VERSION 5.8 ;
BUSBITCHARS "[]" ;
DIVIDERCHAR "/" ;
UNITS
    DATABASE MICRONS 1000 ;
END UNITS

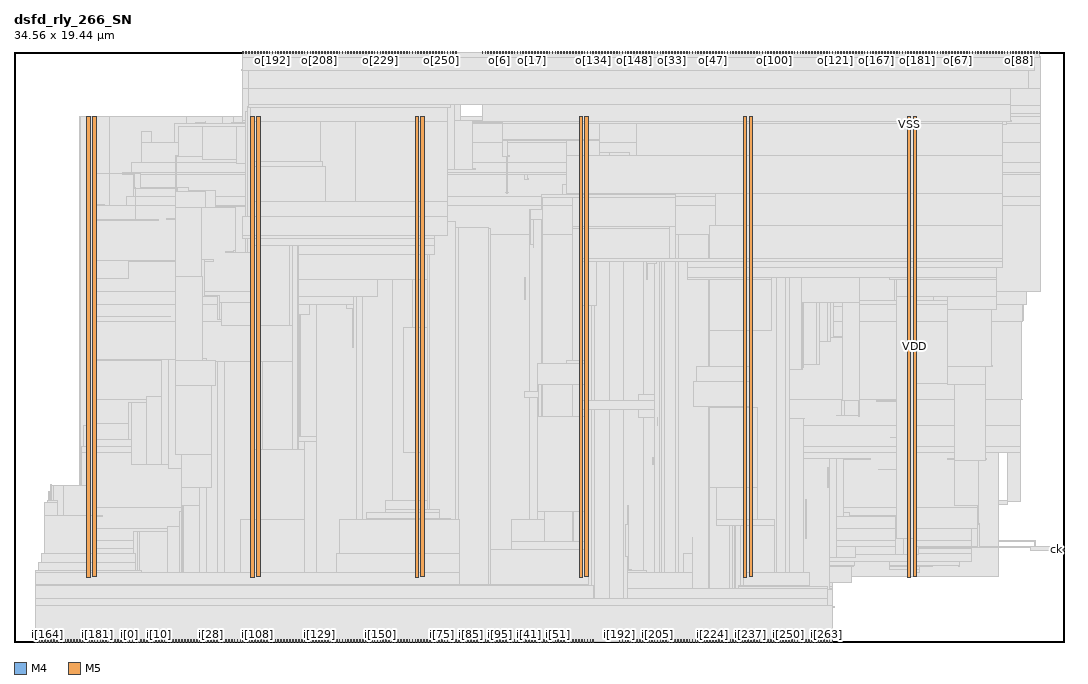
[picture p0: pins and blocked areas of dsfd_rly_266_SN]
MACRO dsfd_rly_266_SN
  FOREIGN dsfd_rly_266_SN 0 0 ;
  CLASS BLOCK ;
  SIZE 34.56 BY 19.44 ;
  PIN ck
    DIRECTION INPUT ;
    USE SIGNAL ;
    PORT
      LAYER M4 ;
        RECT  34.476 3.024 34.56 3.048 ;
    END
  END ck
  PIN i[0]
    DIRECTION INPUT ;
    USE SIGNAL ;
    PORT
      LAYER M5 ;
        RECT  3.792 0 3.816 0.084 ;
    END
  END i[0]
  PIN i[100]
    DIRECTION INPUT ;
    USE SIGNAL ;
    PORT
      LAYER M5 ;
        RECT  7.248 0 7.272 0.084 ;
    END
  END i[100]
  PIN i[101]
    DIRECTION INPUT ;
    USE SIGNAL ;
    PORT
      LAYER M5 ;
        RECT  7.344 0 7.368 0.084 ;
    END
  END i[101]
  PIN i[102]
    DIRECTION INPUT ;
    USE SIGNAL ;
    PORT
      LAYER M5 ;
        RECT  7.44 0 7.464 0.084 ;
    END
  END i[102]
  PIN i[103]
    DIRECTION INPUT ;
    USE SIGNAL ;
    PORT
      LAYER M5 ;
        RECT  7.536 0 7.56 0.084 ;
    END
  END i[103]
  PIN i[104]
    DIRECTION INPUT ;
    USE SIGNAL ;
    PORT
      LAYER M5 ;
        RECT  7.632 0 7.656 0.084 ;
    END
  END i[104]
  PIN i[105]
    DIRECTION INPUT ;
    USE SIGNAL ;
    PORT
      LAYER M5 ;
        RECT  7.728 0 7.752 0.084 ;
    END
  END i[105]
  PIN i[106]
    DIRECTION INPUT ;
    USE SIGNAL ;
    PORT
      LAYER M5 ;
        RECT  7.824 0 7.848 0.084 ;
    END
  END i[106]
  PIN i[107]
    DIRECTION INPUT ;
    USE SIGNAL ;
    PORT
      LAYER M5 ;
        RECT  7.92 0 7.944 0.084 ;
    END
  END i[107]
  PIN i[108]
    DIRECTION INPUT ;
    USE SIGNAL ;
    PORT
      LAYER M5 ;
        RECT  8.016 0 8.04 0.084 ;
    END
  END i[108]
  PIN i[109]
    DIRECTION INPUT ;
    USE SIGNAL ;
    PORT
      LAYER M5 ;
        RECT  8.112 0 8.136 0.084 ;
    END
  END i[109]
  PIN i[10]
    DIRECTION INPUT ;
    USE SIGNAL ;
    PORT
      LAYER M5 ;
        RECT  4.752 0 4.776 0.084 ;
    END
  END i[10]
  PIN i[110]
    DIRECTION INPUT ;
    USE SIGNAL ;
    PORT
      LAYER M5 ;
        RECT  8.208 0 8.232 0.084 ;
    END
  END i[110]
  PIN i[111]
    DIRECTION INPUT ;
    USE SIGNAL ;
    PORT
      LAYER M5 ;
        RECT  8.304 0 8.328 0.084 ;
    END
  END i[111]
  PIN i[112]
    DIRECTION INPUT ;
    USE SIGNAL ;
    PORT
      LAYER M5 ;
        RECT  8.4 0 8.424 0.084 ;
    END
  END i[112]
  PIN i[113]
    DIRECTION INPUT ;
    USE SIGNAL ;
    PORT
      LAYER M5 ;
        RECT  8.496 0 8.52 0.084 ;
    END
  END i[113]
  PIN i[114]
    DIRECTION INPUT ;
    USE SIGNAL ;
    PORT
      LAYER M5 ;
        RECT  8.592 0 8.616 0.084 ;
    END
  END i[114]
  PIN i[115]
    DIRECTION INPUT ;
    USE SIGNAL ;
    PORT
      LAYER M5 ;
        RECT  8.688 0 8.712 0.084 ;
    END
  END i[115]
  PIN i[116]
    DIRECTION INPUT ;
    USE SIGNAL ;
    PORT
      LAYER M5 ;
        RECT  8.784 0 8.808 0.084 ;
    END
  END i[116]
  PIN i[117]
    DIRECTION INPUT ;
    USE SIGNAL ;
    PORT
      LAYER M5 ;
        RECT  8.88 0 8.904 0.084 ;
    END
  END i[117]
  PIN i[118]
    DIRECTION INPUT ;
    USE SIGNAL ;
    PORT
      LAYER M5 ;
        RECT  8.976 0 9 0.084 ;
    END
  END i[118]
  PIN i[119]
    DIRECTION INPUT ;
    USE SIGNAL ;
    PORT
      LAYER M5 ;
        RECT  9.072 0 9.096 0.084 ;
    END
  END i[119]
  PIN i[11]
    DIRECTION INPUT ;
    USE SIGNAL ;
    PORT
      LAYER M5 ;
        RECT  4.848 0 4.872 0.084 ;
    END
  END i[11]
  PIN i[120]
    DIRECTION INPUT ;
    USE SIGNAL ;
    PORT
      LAYER M5 ;
        RECT  9.168 0 9.192 0.084 ;
    END
  END i[120]
  PIN i[121]
    DIRECTION INPUT ;
    USE SIGNAL ;
    PORT
      LAYER M5 ;
        RECT  9.264 0 9.288 0.084 ;
    END
  END i[121]
  PIN i[122]
    DIRECTION INPUT ;
    USE SIGNAL ;
    PORT
      LAYER M5 ;
        RECT  9.36 0 9.384 0.084 ;
    END
  END i[122]
  PIN i[123]
    DIRECTION INPUT ;
    USE SIGNAL ;
    PORT
      LAYER M5 ;
        RECT  9.456 0 9.48 0.084 ;
    END
  END i[123]
  PIN i[124]
    DIRECTION INPUT ;
    USE SIGNAL ;
    PORT
      LAYER M5 ;
        RECT  9.552 0 9.576 0.084 ;
    END
  END i[124]
  PIN i[125]
    DIRECTION INPUT ;
    USE SIGNAL ;
    PORT
      LAYER M5 ;
        RECT  9.648 0 9.672 0.084 ;
    END
  END i[125]
  PIN i[126]
    DIRECTION INPUT ;
    USE SIGNAL ;
    PORT
      LAYER M5 ;
        RECT  9.744 0 9.768 0.084 ;
    END
  END i[126]
  PIN i[127]
    DIRECTION INPUT ;
    USE SIGNAL ;
    PORT
      LAYER M5 ;
        RECT  9.84 0 9.864 0.084 ;
    END
  END i[127]
  PIN i[128]
    DIRECTION INPUT ;
    USE SIGNAL ;
    PORT
      LAYER M5 ;
        RECT  9.936 0 9.96 0.084 ;
    END
  END i[128]
  PIN i[129]
    DIRECTION INPUT ;
    USE SIGNAL ;
    PORT
      LAYER M5 ;
        RECT  10.032 0 10.056 0.084 ;
    END
  END i[129]
  PIN i[12]
    DIRECTION INPUT ;
    USE SIGNAL ;
    PORT
      LAYER M5 ;
        RECT  4.944 0 4.968 0.084 ;
    END
  END i[12]
  PIN i[130]
    DIRECTION INPUT ;
    USE SIGNAL ;
    PORT
      LAYER M5 ;
        RECT  10.128 0 10.152 0.084 ;
    END
  END i[130]
  PIN i[131]
    DIRECTION INPUT ;
    USE SIGNAL ;
    PORT
      LAYER M5 ;
        RECT  10.224 0 10.248 0.084 ;
    END
  END i[131]
  PIN i[132]
    DIRECTION INPUT ;
    USE SIGNAL ;
    PORT
      LAYER M5 ;
        RECT  10.32 0 10.344 0.084 ;
    END
  END i[132]
  PIN i[133]
    DIRECTION INPUT ;
    USE SIGNAL ;
    PORT
      LAYER M5 ;
        RECT  10.416 0 10.44 0.084 ;
    END
  END i[133]
  PIN i[134]
    DIRECTION INPUT ;
    USE SIGNAL ;
    PORT
      LAYER M5 ;
        RECT  10.512 0 10.536 0.084 ;
    END
  END i[134]
  PIN i[135]
    DIRECTION INPUT ;
    USE SIGNAL ;
    PORT
      LAYER M5 ;
        RECT  10.608 0 10.632 0.084 ;
    END
  END i[135]
  PIN i[136]
    DIRECTION INPUT ;
    USE SIGNAL ;
    PORT
      LAYER M5 ;
        RECT  10.704 0 10.728 0.084 ;
    END
  END i[136]
  PIN i[137]
    DIRECTION INPUT ;
    USE SIGNAL ;
    PORT
      LAYER M5 ;
        RECT  10.8 0 10.824 0.084 ;
    END
  END i[137]
  PIN i[138]
    DIRECTION INPUT ;
    USE SIGNAL ;
    PORT
      LAYER M5 ;
        RECT  10.896 0 10.92 0.084 ;
    END
  END i[138]
  PIN i[139]
    DIRECTION INPUT ;
    USE SIGNAL ;
    PORT
      LAYER M5 ;
        RECT  10.992 0 11.016 0.084 ;
    END
  END i[139]
  PIN i[13]
    DIRECTION INPUT ;
    USE SIGNAL ;
    PORT
      LAYER M5 ;
        RECT  5.04 0 5.064 0.084 ;
    END
  END i[13]
  PIN i[140]
    DIRECTION INPUT ;
    USE SIGNAL ;
    PORT
      LAYER M5 ;
        RECT  11.088 0 11.112 0.084 ;
    END
  END i[140]
  PIN i[141]
    DIRECTION INPUT ;
    USE SIGNAL ;
    PORT
      LAYER M5 ;
        RECT  11.184 0 11.208 0.084 ;
    END
  END i[141]
  PIN i[142]
    DIRECTION INPUT ;
    USE SIGNAL ;
    PORT
      LAYER M5 ;
        RECT  11.28 0 11.304 0.084 ;
    END
  END i[142]
  PIN i[143]
    DIRECTION INPUT ;
    USE SIGNAL ;
    PORT
      LAYER M5 ;
        RECT  11.376 0 11.4 0.084 ;
    END
  END i[143]
  PIN i[144]
    DIRECTION INPUT ;
    USE SIGNAL ;
    PORT
      LAYER M5 ;
        RECT  11.472 0 11.496 0.084 ;
    END
  END i[144]
  PIN i[145]
    DIRECTION INPUT ;
    USE SIGNAL ;
    PORT
      LAYER M5 ;
        RECT  11.568 0 11.592 0.084 ;
    END
  END i[145]
  PIN i[146]
    DIRECTION INPUT ;
    USE SIGNAL ;
    PORT
      LAYER M5 ;
        RECT  11.664 0 11.688 0.084 ;
    END
  END i[146]
  PIN i[147]
    DIRECTION INPUT ;
    USE SIGNAL ;
    PORT
      LAYER M5 ;
        RECT  11.76 0 11.784 0.084 ;
    END
  END i[147]
  PIN i[148]
    DIRECTION INPUT ;
    USE SIGNAL ;
    PORT
      LAYER M5 ;
        RECT  11.856 0 11.88 0.084 ;
    END
  END i[148]
  PIN i[149]
    DIRECTION INPUT ;
    USE SIGNAL ;
    PORT
      LAYER M5 ;
        RECT  11.952 0 11.976 0.084 ;
    END
  END i[149]
  PIN i[14]
    DIRECTION INPUT ;
    USE SIGNAL ;
    PORT
      LAYER M5 ;
        RECT  5.136 0 5.16 0.084 ;
    END
  END i[14]
  PIN i[150]
    DIRECTION INPUT ;
    USE SIGNAL ;
    PORT
      LAYER M5 ;
        RECT  12.048 0 12.072 0.084 ;
    END
  END i[150]
  PIN i[151]
    DIRECTION INPUT ;
    USE SIGNAL ;
    PORT
      LAYER M5 ;
        RECT  12.144 0 12.168 0.084 ;
    END
  END i[151]
  PIN i[152]
    DIRECTION INPUT ;
    USE SIGNAL ;
    PORT
      LAYER M5 ;
        RECT  12.24 0 12.264 0.084 ;
    END
  END i[152]
  PIN i[153]
    DIRECTION INPUT ;
    USE SIGNAL ;
    PORT
      LAYER M5 ;
        RECT  12.336 0 12.36 0.084 ;
    END
  END i[153]
  PIN i[154]
    DIRECTION INPUT ;
    USE SIGNAL ;
    PORT
      LAYER M5 ;
        RECT  12.432 0 12.456 0.084 ;
    END
  END i[154]
  PIN i[155]
    DIRECTION INPUT ;
    USE SIGNAL ;
    PORT
      LAYER M5 ;
        RECT  12.528 0 12.552 0.084 ;
    END
  END i[155]
  PIN i[156]
    DIRECTION INPUT ;
    USE SIGNAL ;
    PORT
      LAYER M5 ;
        RECT  12.624 0 12.648 0.084 ;
    END
  END i[156]
  PIN i[157]
    DIRECTION INPUT ;
    USE SIGNAL ;
    PORT
      LAYER M5 ;
        RECT  12.72 0 12.744 0.084 ;
    END
  END i[157]
  PIN i[158]
    DIRECTION INPUT ;
    USE SIGNAL ;
    PORT
      LAYER M5 ;
        RECT  12.816 0 12.84 0.084 ;
    END
  END i[158]
  PIN i[159]
    DIRECTION INPUT ;
    USE SIGNAL ;
    PORT
      LAYER M5 ;
        RECT  12.912 0 12.936 0.084 ;
    END
  END i[159]
  PIN i[15]
    DIRECTION INPUT ;
    USE SIGNAL ;
    PORT
      LAYER M5 ;
        RECT  5.232 0 5.256 0.084 ;
    END
  END i[15]
  PIN i[160]
    DIRECTION INPUT ;
    USE SIGNAL ;
    PORT
      LAYER M5 ;
        RECT  0.72 0 0.744 0.084 ;
    END
  END i[160]
  PIN i[161]
    DIRECTION INPUT ;
    USE SIGNAL ;
    PORT
      LAYER M5 ;
        RECT  0.816 0 0.84 0.084 ;
    END
  END i[161]
  PIN i[162]
    DIRECTION INPUT ;
    USE SIGNAL ;
    PORT
      LAYER M5 ;
        RECT  0.912 0 0.936 0.084 ;
    END
  END i[162]
  PIN i[163]
    DIRECTION INPUT ;
    USE SIGNAL ;
    PORT
      LAYER M5 ;
        RECT  1.008 0 1.032 0.084 ;
    END
  END i[163]
  PIN i[164]
    DIRECTION INPUT ;
    USE SIGNAL ;
    PORT
      LAYER M5 ;
        RECT  1.104 0 1.128 0.084 ;
    END
  END i[164]
  PIN i[165]
    DIRECTION INPUT ;
    USE SIGNAL ;
    PORT
      LAYER M5 ;
        RECT  1.2 0 1.224 0.084 ;
    END
  END i[165]
  PIN i[166]
    DIRECTION INPUT ;
    USE SIGNAL ;
    PORT
      LAYER M5 ;
        RECT  1.296 0 1.32 0.084 ;
    END
  END i[166]
  PIN i[167]
    DIRECTION INPUT ;
    USE SIGNAL ;
    PORT
      LAYER M5 ;
        RECT  1.392 0 1.416 0.084 ;
    END
  END i[167]
  PIN i[168]
    DIRECTION INPUT ;
    USE SIGNAL ;
    PORT
      LAYER M5 ;
        RECT  1.488 0 1.512 0.084 ;
    END
  END i[168]
  PIN i[169]
    DIRECTION INPUT ;
    USE SIGNAL ;
    PORT
      LAYER M5 ;
        RECT  1.584 0 1.608 0.084 ;
    END
  END i[169]
  PIN i[16]
    DIRECTION INPUT ;
    USE SIGNAL ;
    PORT
      LAYER M5 ;
        RECT  5.328 0 5.352 0.084 ;
    END
  END i[16]
  PIN i[170]
    DIRECTION INPUT ;
    USE SIGNAL ;
    PORT
      LAYER M5 ;
        RECT  1.68 0 1.704 0.084 ;
    END
  END i[170]
  PIN i[171]
    DIRECTION INPUT ;
    USE SIGNAL ;
    PORT
      LAYER M5 ;
        RECT  1.776 0 1.8 0.084 ;
    END
  END i[171]
  PIN i[172]
    DIRECTION INPUT ;
    USE SIGNAL ;
    PORT
      LAYER M5 ;
        RECT  1.872 0 1.896 0.084 ;
    END
  END i[172]
  PIN i[173]
    DIRECTION INPUT ;
    USE SIGNAL ;
    PORT
      LAYER M5 ;
        RECT  1.968 0 1.992 0.084 ;
    END
  END i[173]
  PIN i[174]
    DIRECTION INPUT ;
    USE SIGNAL ;
    PORT
      LAYER M5 ;
        RECT  2.064 0 2.088 0.084 ;
    END
  END i[174]
  PIN i[175]
    DIRECTION INPUT ;
    USE SIGNAL ;
    PORT
      LAYER M5 ;
        RECT  2.16 0 2.184 0.084 ;
    END
  END i[175]
  PIN i[176]
    DIRECTION INPUT ;
    USE SIGNAL ;
    PORT
      LAYER M5 ;
        RECT  2.256 0 2.28 0.084 ;
    END
  END i[176]
  PIN i[177]
    DIRECTION INPUT ;
    USE SIGNAL ;
    PORT
      LAYER M5 ;
        RECT  2.352 0 2.376 0.084 ;
    END
  END i[177]
  PIN i[178]
    DIRECTION INPUT ;
    USE SIGNAL ;
    PORT
      LAYER M5 ;
        RECT  2.448 0 2.472 0.084 ;
    END
  END i[178]
  PIN i[179]
    DIRECTION INPUT ;
    USE SIGNAL ;
    PORT
      LAYER M5 ;
        RECT  2.544 0 2.568 0.084 ;
    END
  END i[179]
  PIN i[17]
    DIRECTION INPUT ;
    USE SIGNAL ;
    PORT
      LAYER M5 ;
        RECT  5.424 0 5.448 0.084 ;
    END
  END i[17]
  PIN i[180]
    DIRECTION INPUT ;
    USE SIGNAL ;
    PORT
      LAYER M5 ;
        RECT  2.64 0 2.664 0.084 ;
    END
  END i[180]
  PIN i[181]
    DIRECTION INPUT ;
    USE SIGNAL ;
    PORT
      LAYER M5 ;
        RECT  2.736 0 2.76 0.084 ;
    END
  END i[181]
  PIN i[182]
    DIRECTION INPUT ;
    USE SIGNAL ;
    PORT
      LAYER M5 ;
        RECT  2.832 0 2.856 0.084 ;
    END
  END i[182]
  PIN i[183]
    DIRECTION INPUT ;
    USE SIGNAL ;
    PORT
      LAYER M5 ;
        RECT  2.928 0 2.952 0.084 ;
    END
  END i[183]
  PIN i[184]
    DIRECTION INPUT ;
    USE SIGNAL ;
    PORT
      LAYER M5 ;
        RECT  3.024 0 3.048 0.084 ;
    END
  END i[184]
  PIN i[185]
    DIRECTION INPUT ;
    USE SIGNAL ;
    PORT
      LAYER M5 ;
        RECT  3.12 0 3.144 0.084 ;
    END
  END i[185]
  PIN i[186]
    DIRECTION INPUT ;
    USE SIGNAL ;
    PORT
      LAYER M5 ;
        RECT  3.216 0 3.24 0.084 ;
    END
  END i[186]
  PIN i[187]
    DIRECTION INPUT ;
    USE SIGNAL ;
    PORT
      LAYER M5 ;
        RECT  3.312 0 3.336 0.084 ;
    END
  END i[187]
  PIN i[188]
    DIRECTION INPUT ;
    USE SIGNAL ;
    PORT
      LAYER M5 ;
        RECT  3.408 0 3.432 0.084 ;
    END
  END i[188]
  PIN i[189]
    DIRECTION INPUT ;
    USE SIGNAL ;
    PORT
      LAYER M5 ;
        RECT  3.504 0 3.528 0.084 ;
    END
  END i[189]
  PIN i[18]
    DIRECTION INPUT ;
    USE SIGNAL ;
    PORT
      LAYER M5 ;
        RECT  5.52 0 5.544 0.084 ;
    END
  END i[18]
  PIN i[190]
    DIRECTION INPUT ;
    USE SIGNAL ;
    PORT
      LAYER M5 ;
        RECT  3.6 0 3.624 0.084 ;
    END
  END i[190]
  PIN i[191]
    DIRECTION INPUT ;
    USE SIGNAL ;
    PORT
      LAYER M5 ;
        RECT  3.696 0 3.72 0.084 ;
    END
  END i[191]
  PIN i[192]
    DIRECTION INPUT ;
    USE SIGNAL ;
    PORT
      LAYER M5 ;
        RECT  19.92 0 19.944 0.084 ;
    END
  END i[192]
  PIN i[193]
    DIRECTION INPUT ;
    USE SIGNAL ;
    PORT
      LAYER M5 ;
        RECT  20.016 0 20.04 0.084 ;
    END
  END i[193]
  PIN i[194]
    DIRECTION INPUT ;
    USE SIGNAL ;
    PORT
      LAYER M5 ;
        RECT  20.112 0 20.136 0.084 ;
    END
  END i[194]
  PIN i[195]
    DIRECTION INPUT ;
    USE SIGNAL ;
    PORT
      LAYER M5 ;
        RECT  20.208 0 20.232 0.084 ;
    END
  END i[195]
  PIN i[196]
    DIRECTION INPUT ;
    USE SIGNAL ;
    PORT
      LAYER M5 ;
        RECT  20.304 0 20.328 0.084 ;
    END
  END i[196]
  PIN i[197]
    DIRECTION INPUT ;
    USE SIGNAL ;
    PORT
      LAYER M5 ;
        RECT  20.4 0 20.424 0.084 ;
    END
  END i[197]
  PIN i[198]
    DIRECTION INPUT ;
    USE SIGNAL ;
    PORT
      LAYER M5 ;
        RECT  20.496 0 20.52 0.084 ;
    END
  END i[198]
  PIN i[199]
    DIRECTION INPUT ;
    USE SIGNAL ;
    PORT
      LAYER M5 ;
        RECT  20.592 0 20.616 0.084 ;
    END
  END i[199]
  PIN i[19]
    DIRECTION INPUT ;
    USE SIGNAL ;
    PORT
      LAYER M5 ;
        RECT  5.616 0 5.64 0.084 ;
    END
  END i[19]
  PIN i[1]
    DIRECTION INPUT ;
    USE SIGNAL ;
    PORT
      LAYER M5 ;
        RECT  3.888 0 3.912 0.084 ;
    END
  END i[1]
  PIN i[200]
    DIRECTION INPUT ;
    USE SIGNAL ;
    PORT
      LAYER M5 ;
        RECT  20.688 0 20.712 0.084 ;
    END
  END i[200]
  PIN i[201]
    DIRECTION INPUT ;
    USE SIGNAL ;
    PORT
      LAYER M5 ;
        RECT  20.784 0 20.808 0.084 ;
    END
  END i[201]
  PIN i[202]
    DIRECTION INPUT ;
    USE SIGNAL ;
    PORT
      LAYER M5 ;
        RECT  20.88 0 20.904 0.084 ;
    END
  END i[202]
  PIN i[203]
    DIRECTION INPUT ;
    USE SIGNAL ;
    PORT
      LAYER M5 ;
        RECT  20.976 0 21 0.084 ;
    END
  END i[203]
  PIN i[204]
    DIRECTION INPUT ;
    USE SIGNAL ;
    PORT
      LAYER M5 ;
        RECT  21.072 0 21.096 0.084 ;
    END
  END i[204]
  PIN i[205]
    DIRECTION INPUT ;
    USE SIGNAL ;
    PORT
      LAYER M5 ;
        RECT  21.168 0 21.192 0.084 ;
    END
  END i[205]
  PIN i[206]
    DIRECTION INPUT ;
    USE SIGNAL ;
    PORT
      LAYER M5 ;
        RECT  21.264 0 21.288 0.084 ;
    END
  END i[206]
  PIN i[207]
    DIRECTION INPUT ;
    USE SIGNAL ;
    PORT
      LAYER M5 ;
        RECT  21.36 0 21.384 0.084 ;
    END
  END i[207]
  PIN i[208]
    DIRECTION INPUT ;
    USE SIGNAL ;
    PORT
      LAYER M5 ;
        RECT  21.456 0 21.48 0.084 ;
    END
  END i[208]
  PIN i[209]
    DIRECTION INPUT ;
    USE SIGNAL ;
    PORT
      LAYER M5 ;
        RECT  21.552 0 21.576 0.084 ;
    END
  END i[209]
  PIN i[20]
    DIRECTION INPUT ;
    USE SIGNAL ;
    PORT
      LAYER M5 ;
        RECT  5.712 0 5.736 0.084 ;
    END
  END i[20]
  PIN i[210]
    DIRECTION INPUT ;
    USE SIGNAL ;
    PORT
      LAYER M5 ;
        RECT  21.648 0 21.672 0.084 ;
    END
  END i[210]
  PIN i[211]
    DIRECTION INPUT ;
    USE SIGNAL ;
    PORT
      LAYER M5 ;
        RECT  21.744 0 21.768 0.084 ;
    END
  END i[211]
  PIN i[212]
    DIRECTION INPUT ;
    USE SIGNAL ;
    PORT
      LAYER M5 ;
        RECT  21.84 0 21.864 0.084 ;
    END
  END i[212]
  PIN i[213]
    DIRECTION INPUT ;
    USE SIGNAL ;
    PORT
      LAYER M5 ;
        RECT  21.936 0 21.96 0.084 ;
    END
  END i[213]
  PIN i[214]
    DIRECTION INPUT ;
    USE SIGNAL ;
    PORT
      LAYER M5 ;
        RECT  22.032 0 22.056 0.084 ;
    END
  END i[214]
  PIN i[215]
    DIRECTION INPUT ;
    USE SIGNAL ;
    PORT
      LAYER M5 ;
        RECT  22.128 0 22.152 0.084 ;
    END
  END i[215]
  PIN i[216]
    DIRECTION INPUT ;
    USE SIGNAL ;
    PORT
      LAYER M5 ;
        RECT  22.224 0 22.248 0.084 ;
    END
  END i[216]
  PIN i[217]
    DIRECTION INPUT ;
    USE SIGNAL ;
    PORT
      LAYER M5 ;
        RECT  22.32 0 22.344 0.084 ;
    END
  END i[217]
  PIN i[218]
    DIRECTION INPUT ;
    USE SIGNAL ;
    PORT
      LAYER M5 ;
        RECT  22.416 0 22.44 0.084 ;
    END
  END i[218]
  PIN i[219]
    DIRECTION INPUT ;
    USE SIGNAL ;
    PORT
      LAYER M5 ;
        RECT  22.512 0 22.536 0.084 ;
    END
  END i[219]
  PIN i[21]
    DIRECTION INPUT ;
    USE SIGNAL ;
    PORT
      LAYER M5 ;
        RECT  5.808 0 5.832 0.084 ;
    END
  END i[21]
  PIN i[220]
    DIRECTION INPUT ;
    USE SIGNAL ;
    PORT
      LAYER M5 ;
        RECT  22.608 0 22.632 0.084 ;
    END
  END i[220]
  PIN i[221]
    DIRECTION INPUT ;
    USE SIGNAL ;
    PORT
      LAYER M5 ;
        RECT  22.704 0 22.728 0.084 ;
    END
  END i[221]
  PIN i[222]
    DIRECTION INPUT ;
    USE SIGNAL ;
    PORT
      LAYER M5 ;
        RECT  22.8 0 22.824 0.084 ;
    END
  END i[222]
  PIN i[223]
    DIRECTION INPUT ;
    USE SIGNAL ;
    PORT
      LAYER M5 ;
        RECT  22.896 0 22.92 0.084 ;
    END
  END i[223]
  PIN i[224]
    DIRECTION INPUT ;
    USE SIGNAL ;
    PORT
      LAYER M5 ;
        RECT  22.992 0 23.016 0.084 ;
    END
  END i[224]
  PIN i[225]
    DIRECTION INPUT ;
    USE SIGNAL ;
    PORT
      LAYER M5 ;
        RECT  23.088 0 23.112 0.084 ;
    END
  END i[225]
  PIN i[226]
    DIRECTION INPUT ;
    USE SIGNAL ;
    PORT
      LAYER M5 ;
        RECT  23.184 0 23.208 0.084 ;
    END
  END i[226]
  PIN i[227]
    DIRECTION INPUT ;
    USE SIGNAL ;
    PORT
      LAYER M5 ;
        RECT  23.28 0 23.304 0.084 ;
    END
  END i[227]
  PIN i[228]
    DIRECTION INPUT ;
    USE SIGNAL ;
    PORT
      LAYER M5 ;
        RECT  23.376 0 23.4 0.084 ;
    END
  END i[228]
  PIN i[229]
    DIRECTION INPUT ;
    USE SIGNAL ;
    PORT
      LAYER M5 ;
        RECT  23.472 0 23.496 0.084 ;
    END
  END i[229]
  PIN i[22]
    DIRECTION INPUT ;
    USE SIGNAL ;
    PORT
      LAYER M5 ;
        RECT  5.904 0 5.928 0.084 ;
    END
  END i[22]
  PIN i[230]
    DIRECTION INPUT ;
    USE SIGNAL ;
    PORT
      LAYER M5 ;
        RECT  23.568 0 23.592 0.084 ;
    END
  END i[230]
  PIN i[231]
    DIRECTION INPUT ;
    USE SIGNAL ;
    PORT
      LAYER M5 ;
        RECT  23.664 0 23.688 0.084 ;
    END
  END i[231]
  PIN i[232]
    DIRECTION INPUT ;
    USE SIGNAL ;
    PORT
      LAYER M5 ;
        RECT  23.76 0 23.784 0.084 ;
    END
  END i[232]
  PIN i[233]
    DIRECTION INPUT ;
    USE SIGNAL ;
    PORT
      LAYER M5 ;
        RECT  23.856 0 23.88 0.084 ;
    END
  END i[233]
  PIN i[234]
    DIRECTION INPUT ;
    USE SIGNAL ;
    PORT
      LAYER M5 ;
        RECT  23.952 0 23.976 0.084 ;
    END
  END i[234]
  PIN i[235]
    DIRECTION INPUT ;
    USE SIGNAL ;
    PORT
      LAYER M5 ;
        RECT  24.048 0 24.072 0.084 ;
    END
  END i[235]
  PIN i[236]
    DIRECTION INPUT ;
    USE SIGNAL ;
    PORT
      LAYER M5 ;
        RECT  24.144 0 24.168 0.084 ;
    END
  END i[236]
  PIN i[237]
    DIRECTION INPUT ;
    USE SIGNAL ;
    PORT
      LAYER M5 ;
        RECT  24.24 0 24.264 0.084 ;
    END
  END i[237]
  PIN i[238]
    DIRECTION INPUT ;
    USE SIGNAL ;
    PORT
      LAYER M5 ;
        RECT  24.336 0 24.36 0.084 ;
    END
  END i[238]
  PIN i[239]
    DIRECTION INPUT ;
    USE SIGNAL ;
    PORT
      LAYER M5 ;
        RECT  24.432 0 24.456 0.084 ;
    END
  END i[239]
  PIN i[23]
    DIRECTION INPUT ;
    USE SIGNAL ;
    PORT
      LAYER M5 ;
        RECT  6 0 6.024 0.084 ;
    END
  END i[23]
  PIN i[240]
    DIRECTION INPUT ;
    USE SIGNAL ;
    PORT
      LAYER M5 ;
        RECT  24.528 0 24.552 0.084 ;
    END
  END i[240]
  PIN i[241]
    DIRECTION INPUT ;
    USE SIGNAL ;
    PORT
      LAYER M5 ;
        RECT  24.624 0 24.648 0.084 ;
    END
  END i[241]
  PIN i[242]
    DIRECTION INPUT ;
    USE SIGNAL ;
    PORT
      LAYER M5 ;
        RECT  24.72 0 24.744 0.084 ;
    END
  END i[242]
  PIN i[243]
    DIRECTION INPUT ;
    USE SIGNAL ;
    PORT
      LAYER M5 ;
        RECT  24.816 0 24.84 0.084 ;
    END
  END i[243]
  PIN i[244]
    DIRECTION INPUT ;
    USE SIGNAL ;
    PORT
      LAYER M5 ;
        RECT  24.912 0 24.936 0.084 ;
    END
  END i[244]
  PIN i[245]
    DIRECTION INPUT ;
    USE SIGNAL ;
    PORT
      LAYER M5 ;
        RECT  25.008 0 25.032 0.084 ;
    END
  END i[245]
  PIN i[246]
    DIRECTION INPUT ;
    USE SIGNAL ;
    PORT
      LAYER M5 ;
        RECT  25.104 0 25.128 0.084 ;
    END
  END i[246]
  PIN i[247]
    DIRECTION INPUT ;
    USE SIGNAL ;
    PORT
      LAYER M5 ;
        RECT  25.2 0 25.224 0.084 ;
    END
  END i[247]
  PIN i[248]
    DIRECTION INPUT ;
    USE SIGNAL ;
    PORT
      LAYER M5 ;
        RECT  25.296 0 25.32 0.084 ;
    END
  END i[248]
  PIN i[249]
    DIRECTION INPUT ;
    USE SIGNAL ;
    PORT
      LAYER M5 ;
        RECT  25.392 0 25.416 0.084 ;
    END
  END i[249]
  PIN i[24]
    DIRECTION INPUT ;
    USE SIGNAL ;
    PORT
      LAYER M5 ;
        RECT  6.096 0 6.12 0.084 ;
    END
  END i[24]
  PIN i[250]
    DIRECTION INPUT ;
    USE SIGNAL ;
    PORT
      LAYER M5 ;
        RECT  25.488 0 25.512 0.084 ;
    END
  END i[250]
  PIN i[251]
    DIRECTION INPUT ;
    USE SIGNAL ;
    PORT
      LAYER M5 ;
        RECT  25.584 0 25.608 0.084 ;
    END
  END i[251]
  PIN i[252]
    DIRECTION INPUT ;
    USE SIGNAL ;
    PORT
      LAYER M5 ;
        RECT  25.68 0 25.704 0.084 ;
    END
  END i[252]
  PIN i[253]
    DIRECTION INPUT ;
    USE SIGNAL ;
    PORT
      LAYER M5 ;
        RECT  25.776 0 25.8 0.084 ;
    END
  END i[253]
  PIN i[254]
    DIRECTION INPUT ;
    USE SIGNAL ;
    PORT
      LAYER M5 ;
        RECT  25.872 0 25.896 0.084 ;
    END
  END i[254]
  PIN i[255]
    DIRECTION INPUT ;
    USE SIGNAL ;
    PORT
      LAYER M5 ;
        RECT  25.968 0 25.992 0.084 ;
    END
  END i[255]
  PIN i[256]
    DIRECTION INPUT ;
    USE SIGNAL ;
    PORT
      LAYER M5 ;
        RECT  26.064 0 26.088 0.084 ;
    END
  END i[256]
  PIN i[257]
    DIRECTION INPUT ;
    USE SIGNAL ;
    PORT
      LAYER M5 ;
        RECT  26.16 0 26.184 0.084 ;
    END
  END i[257]
  PIN i[258]
    DIRECTION INPUT ;
    USE SIGNAL ;
    PORT
      LAYER M5 ;
        RECT  26.256 0 26.28 0.084 ;
    END
  END i[258]
  PIN i[259]
    DIRECTION INPUT ;
    USE SIGNAL ;
    PORT
      LAYER M5 ;
        RECT  26.352 0 26.376 0.084 ;
    END
  END i[259]
  PIN i[25]
    DIRECTION INPUT ;
    USE SIGNAL ;
    PORT
      LAYER M5 ;
        RECT  6.192 0 6.216 0.084 ;
    END
  END i[25]
  PIN i[260]
    DIRECTION INPUT ;
    USE SIGNAL ;
    PORT
      LAYER M5 ;
        RECT  26.448 0 26.472 0.084 ;
    END
  END i[260]
  PIN i[261]
    DIRECTION INPUT ;
    USE SIGNAL ;
    PORT
      LAYER M5 ;
        RECT  26.544 0 26.568 0.084 ;
    END
  END i[261]
  PIN i[262]
    DIRECTION INPUT ;
    USE SIGNAL ;
    PORT
      LAYER M5 ;
        RECT  26.64 0 26.664 0.084 ;
    END
  END i[262]
  PIN i[263]
    DIRECTION INPUT ;
    USE SIGNAL ;
    PORT
      LAYER M5 ;
        RECT  26.736 0 26.76 0.084 ;
    END
  END i[263]
  PIN i[264]
    DIRECTION INPUT ;
    USE SIGNAL ;
    PORT
      LAYER M5 ;
        RECT  26.832 0 26.856 0.084 ;
    END
  END i[264]
  PIN i[265]
    DIRECTION INPUT ;
    USE SIGNAL ;
    PORT
      LAYER M5 ;
        RECT  26.928 0 26.952 0.084 ;
    END
  END i[265]
  PIN i[26]
    DIRECTION INPUT ;
    USE SIGNAL ;
    PORT
      LAYER M5 ;
        RECT  6.288 0 6.312 0.084 ;
    END
  END i[26]
  PIN i[27]
    DIRECTION INPUT ;
    USE SIGNAL ;
    PORT
      LAYER M5 ;
        RECT  6.384 0 6.408 0.084 ;
    END
  END i[27]
  PIN i[28]
    DIRECTION INPUT ;
    USE SIGNAL ;
    PORT
      LAYER M5 ;
        RECT  6.48 0 6.504 0.084 ;
    END
  END i[28]
  PIN i[29]
    DIRECTION INPUT ;
    USE SIGNAL ;
    PORT
      LAYER M5 ;
        RECT  6.576 0 6.6 0.084 ;
    END
  END i[29]
  PIN i[2]
    DIRECTION INPUT ;
    USE SIGNAL ;
    PORT
      LAYER M5 ;
        RECT  3.984 0 4.008 0.084 ;
    END
  END i[2]
  PIN i[30]
    DIRECTION INPUT ;
    USE SIGNAL ;
    PORT
      LAYER M5 ;
        RECT  6.672 0 6.696 0.084 ;
    END
  END i[30]
  PIN i[31]
    DIRECTION INPUT ;
    USE SIGNAL ;
    PORT
      LAYER M5 ;
        RECT  6.768 0 6.792 0.084 ;
    END
  END i[31]
  PIN i[32]
    DIRECTION INPUT ;
    USE SIGNAL ;
    PORT
      LAYER M5 ;
        RECT  16.08 0 16.104 0.084 ;
    END
  END i[32]
  PIN i[33]
    DIRECTION INPUT ;
    USE SIGNAL ;
    PORT
      LAYER M5 ;
        RECT  16.176 0 16.2 0.084 ;
    END
  END i[33]
  PIN i[34]
    DIRECTION INPUT ;
    USE SIGNAL ;
    PORT
      LAYER M5 ;
        RECT  16.272 0 16.296 0.084 ;
    END
  END i[34]
  PIN i[35]
    DIRECTION INPUT ;
    USE SIGNAL ;
    PORT
      LAYER M5 ;
        RECT  16.368 0 16.392 0.084 ;
    END
  END i[35]
  PIN i[36]
    DIRECTION INPUT ;
    USE SIGNAL ;
    PORT
      LAYER M5 ;
        RECT  16.464 0 16.488 0.084 ;
    END
  END i[36]
  PIN i[37]
    DIRECTION INPUT ;
    USE SIGNAL ;
    PORT
      LAYER M5 ;
        RECT  16.56 0 16.584 0.084 ;
    END
  END i[37]
  PIN i[38]
    DIRECTION INPUT ;
    USE SIGNAL ;
    PORT
      LAYER M5 ;
        RECT  16.656 0 16.68 0.084 ;
    END
  END i[38]
  PIN i[39]
    DIRECTION INPUT ;
    USE SIGNAL ;
    PORT
      LAYER M5 ;
        RECT  16.752 0 16.776 0.084 ;
    END
  END i[39]
  PIN i[3]
    DIRECTION INPUT ;
    USE SIGNAL ;
    PORT
      LAYER M5 ;
        RECT  4.08 0 4.104 0.084 ;
    END
  END i[3]
  PIN i[40]
    DIRECTION INPUT ;
    USE SIGNAL ;
    PORT
      LAYER M5 ;
        RECT  16.848 0 16.872 0.084 ;
    END
  END i[40]
  PIN i[41]
    DIRECTION INPUT ;
    USE SIGNAL ;
    PORT
      LAYER M5 ;
        RECT  16.944 0 16.968 0.084 ;
    END
  END i[41]
  PIN i[42]
    DIRECTION INPUT ;
    USE SIGNAL ;
    PORT
      LAYER M5 ;
        RECT  17.04 0 17.064 0.084 ;
    END
  END i[42]
  PIN i[43]
    DIRECTION INPUT ;
    USE SIGNAL ;
    PORT
      LAYER M5 ;
        RECT  17.136 0 17.16 0.084 ;
    END
  END i[43]
  PIN i[44]
    DIRECTION INPUT ;
    USE SIGNAL ;
    PORT
      LAYER M5 ;
        RECT  17.232 0 17.256 0.084 ;
    END
  END i[44]
  PIN i[45]
    DIRECTION INPUT ;
    USE SIGNAL ;
    PORT
      LAYER M5 ;
        RECT  17.328 0 17.352 0.084 ;
    END
  END i[45]
  PIN i[46]
    DIRECTION INPUT ;
    USE SIGNAL ;
    PORT
      LAYER M5 ;
        RECT  17.424 0 17.448 0.084 ;
    END
  END i[46]
  PIN i[47]
    DIRECTION INPUT ;
    USE SIGNAL ;
    PORT
      LAYER M5 ;
        RECT  17.52 0 17.544 0.084 ;
    END
  END i[47]
  PIN i[48]
    DIRECTION INPUT ;
    USE SIGNAL ;
    PORT
      LAYER M5 ;
        RECT  17.616 0 17.64 0.084 ;
    END
  END i[48]
  PIN i[49]
    DIRECTION INPUT ;
    USE SIGNAL ;
    PORT
      LAYER M5 ;
        RECT  17.712 0 17.736 0.084 ;
    END
  END i[49]
  PIN i[4]
    DIRECTION INPUT ;
    USE SIGNAL ;
    PORT
      LAYER M5 ;
        RECT  4.176 0 4.2 0.084 ;
    END
  END i[4]
  PIN i[50]
    DIRECTION INPUT ;
    USE SIGNAL ;
    PORT
      LAYER M5 ;
        RECT  17.808 0 17.832 0.084 ;
    END
  END i[50]
  PIN i[51]
    DIRECTION INPUT ;
    USE SIGNAL ;
    PORT
      LAYER M5 ;
        RECT  17.904 0 17.928 0.084 ;
    END
  END i[51]
  PIN i[52]
    DIRECTION INPUT ;
    USE SIGNAL ;
    PORT
      LAYER M5 ;
        RECT  18 0 18.024 0.084 ;
    END
  END i[52]
  PIN i[53]
    DIRECTION INPUT ;
    USE SIGNAL ;
    PORT
      LAYER M5 ;
        RECT  18.096 0 18.12 0.084 ;
    END
  END i[53]
  PIN i[54]
    DIRECTION INPUT ;
    USE SIGNAL ;
    PORT
      LAYER M5 ;
        RECT  18.192 0 18.216 0.084 ;
    END
  END i[54]
  PIN i[55]
    DIRECTION INPUT ;
    USE SIGNAL ;
    PORT
      LAYER M5 ;
        RECT  18.288 0 18.312 0.084 ;
    END
  END i[55]
  PIN i[56]
    DIRECTION INPUT ;
    USE SIGNAL ;
    PORT
      LAYER M5 ;
        RECT  18.384 0 18.408 0.084 ;
    END
  END i[56]
  PIN i[57]
    DIRECTION INPUT ;
    USE SIGNAL ;
    PORT
      LAYER M5 ;
        RECT  18.48 0 18.504 0.084 ;
    END
  END i[57]
  PIN i[58]
    DIRECTION INPUT ;
    USE SIGNAL ;
    PORT
      LAYER M5 ;
        RECT  18.576 0 18.6 0.084 ;
    END
  END i[58]
  PIN i[59]
    DIRECTION INPUT ;
    USE SIGNAL ;
    PORT
      LAYER M5 ;
        RECT  18.672 0 18.696 0.084 ;
    END
  END i[59]
  PIN i[5]
    DIRECTION INPUT ;
    USE SIGNAL ;
    PORT
      LAYER M5 ;
        RECT  4.272 0 4.296 0.084 ;
    END
  END i[5]
  PIN i[60]
    DIRECTION INPUT ;
    USE SIGNAL ;
    PORT
      LAYER M5 ;
        RECT  18.768 0 18.792 0.084 ;
    END
  END i[60]
  PIN i[61]
    DIRECTION INPUT ;
    USE SIGNAL ;
    PORT
      LAYER M5 ;
        RECT  18.864 0 18.888 0.084 ;
    END
  END i[61]
  PIN i[62]
    DIRECTION INPUT ;
    USE SIGNAL ;
    PORT
      LAYER M5 ;
        RECT  18.96 0 18.984 0.084 ;
    END
  END i[62]
  PIN i[63]
    DIRECTION INPUT ;
    USE SIGNAL ;
    PORT
      LAYER M5 ;
        RECT  19.056 0 19.08 0.084 ;
    END
  END i[63]
  PIN i[64]
    DIRECTION INPUT ;
    USE SIGNAL ;
    PORT
      LAYER M5 ;
        RECT  13.008 0 13.032 0.084 ;
    END
  END i[64]
  PIN i[65]
    DIRECTION INPUT ;
    USE SIGNAL ;
    PORT
      LAYER M5 ;
        RECT  13.104 0 13.128 0.084 ;
    END
  END i[65]
  PIN i[66]
    DIRECTION INPUT ;
    USE SIGNAL ;
    PORT
      LAYER M5 ;
        RECT  13.2 0 13.224 0.084 ;
    END
  END i[66]
  PIN i[67]
    DIRECTION INPUT ;
    USE SIGNAL ;
    PORT
      LAYER M5 ;
        RECT  13.296 0 13.32 0.084 ;
    END
  END i[67]
  PIN i[68]
    DIRECTION INPUT ;
    USE SIGNAL ;
    PORT
      LAYER M5 ;
        RECT  13.392 0 13.416 0.084 ;
    END
  END i[68]
  PIN i[69]
    DIRECTION INPUT ;
    USE SIGNAL ;
    PORT
      LAYER M5 ;
        RECT  13.488 0 13.512 0.084 ;
    END
  END i[69]
  PIN i[6]
    DIRECTION INPUT ;
    USE SIGNAL ;
    PORT
      LAYER M5 ;
        RECT  4.368 0 4.392 0.084 ;
    END
  END i[6]
  PIN i[70]
    DIRECTION INPUT ;
    USE SIGNAL ;
    PORT
      LAYER M5 ;
        RECT  13.584 0 13.608 0.084 ;
    END
  END i[70]
  PIN i[71]
    DIRECTION INPUT ;
    USE SIGNAL ;
    PORT
      LAYER M5 ;
        RECT  13.68 0 13.704 0.084 ;
    END
  END i[71]
  PIN i[72]
    DIRECTION INPUT ;
    USE SIGNAL ;
    PORT
      LAYER M5 ;
        RECT  13.776 0 13.8 0.084 ;
    END
  END i[72]
  PIN i[73]
    DIRECTION INPUT ;
    USE SIGNAL ;
    PORT
      LAYER M5 ;
        RECT  13.872 0 13.896 0.084 ;
    END
  END i[73]
  PIN i[74]
    DIRECTION INPUT ;
    USE SIGNAL ;
    PORT
      LAYER M5 ;
        RECT  13.968 0 13.992 0.084 ;
    END
  END i[74]
  PIN i[75]
    DIRECTION INPUT ;
    USE SIGNAL ;
    PORT
      LAYER M5 ;
        RECT  14.064 0 14.088 0.084 ;
    END
  END i[75]
  PIN i[76]
    DIRECTION INPUT ;
    USE SIGNAL ;
    PORT
      LAYER M5 ;
        RECT  14.16 0 14.184 0.084 ;
    END
  END i[76]
  PIN i[77]
    DIRECTION INPUT ;
    USE SIGNAL ;
    PORT
      LAYER M5 ;
        RECT  14.256 0 14.28 0.084 ;
    END
  END i[77]
  PIN i[78]
    DIRECTION INPUT ;
    USE SIGNAL ;
    PORT
      LAYER M5 ;
        RECT  14.352 0 14.376 0.084 ;
    END
  END i[78]
  PIN i[79]
    DIRECTION INPUT ;
    USE SIGNAL ;
    PORT
      LAYER M5 ;
        RECT  14.448 0 14.472 0.084 ;
    END
  END i[79]
  PIN i[7]
    DIRECTION INPUT ;
    USE SIGNAL ;
    PORT
      LAYER M5 ;
        RECT  4.464 0 4.488 0.084 ;
    END
  END i[7]
  PIN i[80]
    DIRECTION INPUT ;
    USE SIGNAL ;
    PORT
      LAYER M5 ;
        RECT  14.544 0 14.568 0.084 ;
    END
  END i[80]
  PIN i[81]
    DIRECTION INPUT ;
    USE SIGNAL ;
    PORT
      LAYER M5 ;
        RECT  14.64 0 14.664 0.084 ;
    END
  END i[81]
  PIN i[82]
    DIRECTION INPUT ;
    USE SIGNAL ;
    PORT
      LAYER M5 ;
        RECT  14.736 0 14.76 0.084 ;
    END
  END i[82]
  PIN i[83]
    DIRECTION INPUT ;
    USE SIGNAL ;
    PORT
      LAYER M5 ;
        RECT  14.832 0 14.856 0.084 ;
    END
  END i[83]
  PIN i[84]
    DIRECTION INPUT ;
    USE SIGNAL ;
    PORT
      LAYER M5 ;
        RECT  14.928 0 14.952 0.084 ;
    END
  END i[84]
  PIN i[85]
    DIRECTION INPUT ;
    USE SIGNAL ;
    PORT
      LAYER M5 ;
        RECT  15.024 0 15.048 0.084 ;
    END
  END i[85]
  PIN i[86]
    DIRECTION INPUT ;
    USE SIGNAL ;
    PORT
      LAYER M5 ;
        RECT  15.12 0 15.144 0.084 ;
    END
  END i[86]
  PIN i[87]
    DIRECTION INPUT ;
    USE SIGNAL ;
    PORT
      LAYER M5 ;
        RECT  15.216 0 15.24 0.084 ;
    END
  END i[87]
  PIN i[88]
    DIRECTION INPUT ;
    USE SIGNAL ;
    PORT
      LAYER M5 ;
        RECT  15.312 0 15.336 0.084 ;
    END
  END i[88]
  PIN i[89]
    DIRECTION INPUT ;
    USE SIGNAL ;
    PORT
      LAYER M5 ;
        RECT  15.408 0 15.432 0.084 ;
    END
  END i[89]
  PIN i[8]
    DIRECTION INPUT ;
    USE SIGNAL ;
    PORT
      LAYER M5 ;
        RECT  4.56 0 4.584 0.084 ;
    END
  END i[8]
  PIN i[90]
    DIRECTION INPUT ;
    USE SIGNAL ;
    PORT
      LAYER M5 ;
        RECT  15.504 0 15.528 0.084 ;
    END
  END i[90]
  PIN i[91]
    DIRECTION INPUT ;
    USE SIGNAL ;
    PORT
      LAYER M5 ;
        RECT  15.6 0 15.624 0.084 ;
    END
  END i[91]
  PIN i[92]
    DIRECTION INPUT ;
    USE SIGNAL ;
    PORT
      LAYER M5 ;
        RECT  15.696 0 15.72 0.084 ;
    END
  END i[92]
  PIN i[93]
    DIRECTION INPUT ;
    USE SIGNAL ;
    PORT
      LAYER M5 ;
        RECT  15.792 0 15.816 0.084 ;
    END
  END i[93]
  PIN i[94]
    DIRECTION INPUT ;
    USE SIGNAL ;
    PORT
      LAYER M5 ;
        RECT  15.888 0 15.912 0.084 ;
    END
  END i[94]
  PIN i[95]
    DIRECTION INPUT ;
    USE SIGNAL ;
    PORT
      LAYER M5 ;
        RECT  15.984 0 16.008 0.084 ;
    END
  END i[95]
  PIN i[96]
    DIRECTION INPUT ;
    USE SIGNAL ;
    PORT
      LAYER M5 ;
        RECT  6.864 0 6.888 0.084 ;
    END
  END i[96]
  PIN i[97]
    DIRECTION INPUT ;
    USE SIGNAL ;
    PORT
      LAYER M5 ;
        RECT  6.96 0 6.984 0.084 ;
    END
  END i[97]
  PIN i[98]
    DIRECTION INPUT ;
    USE SIGNAL ;
    PORT
      LAYER M5 ;
        RECT  7.056 0 7.08 0.084 ;
    END
  END i[98]
  PIN i[99]
    DIRECTION INPUT ;
    USE SIGNAL ;
    PORT
      LAYER M5 ;
        RECT  7.152 0 7.176 0.084 ;
    END
  END i[99]
  PIN i[9]
    DIRECTION INPUT ;
    USE SIGNAL ;
    PORT
      LAYER M5 ;
        RECT  4.656 0 4.68 0.084 ;
    END
  END i[9]
  PIN o[0]
    DIRECTION OUTPUT ;
    USE SIGNAL ;
    PORT
      LAYER M5 ;
        RECT  15.408 19.356 15.432 19.44 ;
    END
  END o[0]
  PIN o[100]
    DIRECTION OUTPUT ;
    USE SIGNAL ;
    PORT
      LAYER M5 ;
        RECT  25.008 19.356 25.032 19.44 ;
    END
  END o[100]
  PIN o[101]
    DIRECTION OUTPUT ;
    USE SIGNAL ;
    PORT
      LAYER M5 ;
        RECT  25.104 19.356 25.128 19.44 ;
    END
  END o[101]
  PIN o[102]
    DIRECTION OUTPUT ;
    USE SIGNAL ;
    PORT
      LAYER M5 ;
        RECT  25.2 19.356 25.224 19.44 ;
    END
  END o[102]
  PIN o[103]
    DIRECTION OUTPUT ;
    USE SIGNAL ;
    PORT
      LAYER M5 ;
        RECT  25.296 19.356 25.32 19.44 ;
    END
  END o[103]
  PIN o[104]
    DIRECTION OUTPUT ;
    USE SIGNAL ;
    PORT
      LAYER M5 ;
        RECT  25.392 19.356 25.416 19.44 ;
    END
  END o[104]
  PIN o[105]
    DIRECTION OUTPUT ;
    USE SIGNAL ;
    PORT
      LAYER M5 ;
        RECT  25.488 19.356 25.512 19.44 ;
    END
  END o[105]
  PIN o[106]
    DIRECTION OUTPUT ;
    USE SIGNAL ;
    PORT
      LAYER M5 ;
        RECT  25.584 19.356 25.608 19.44 ;
    END
  END o[106]
  PIN o[107]
    DIRECTION OUTPUT ;
    USE SIGNAL ;
    PORT
      LAYER M5 ;
        RECT  25.68 19.356 25.704 19.44 ;
    END
  END o[107]
  PIN o[108]
    DIRECTION OUTPUT ;
    USE SIGNAL ;
    PORT
      LAYER M5 ;
        RECT  25.776 19.356 25.8 19.44 ;
    END
  END o[108]
  PIN o[109]
    DIRECTION OUTPUT ;
    USE SIGNAL ;
    PORT
      LAYER M5 ;
        RECT  25.872 19.356 25.896 19.44 ;
    END
  END o[109]
  PIN o[10]
    DIRECTION OUTPUT ;
    USE SIGNAL ;
    PORT
      LAYER M5 ;
        RECT  16.368 19.356 16.392 19.44 ;
    END
  END o[10]
  PIN o[110]
    DIRECTION OUTPUT ;
    USE SIGNAL ;
    PORT
      LAYER M5 ;
        RECT  25.968 19.356 25.992 19.44 ;
    END
  END o[110]
  PIN o[111]
    DIRECTION OUTPUT ;
    USE SIGNAL ;
    PORT
      LAYER M5 ;
        RECT  26.064 19.356 26.088 19.44 ;
    END
  END o[111]
  PIN o[112]
    DIRECTION OUTPUT ;
    USE SIGNAL ;
    PORT
      LAYER M5 ;
        RECT  26.16 19.356 26.184 19.44 ;
    END
  END o[112]
  PIN o[113]
    DIRECTION OUTPUT ;
    USE SIGNAL ;
    PORT
      LAYER M5 ;
        RECT  26.256 19.356 26.28 19.44 ;
    END
  END o[113]
  PIN o[114]
    DIRECTION OUTPUT ;
    USE SIGNAL ;
    PORT
      LAYER M5 ;
        RECT  26.352 19.356 26.376 19.44 ;
    END
  END o[114]
  PIN o[115]
    DIRECTION OUTPUT ;
    USE SIGNAL ;
    PORT
      LAYER M5 ;
        RECT  26.448 19.356 26.472 19.44 ;
    END
  END o[115]
  PIN o[116]
    DIRECTION OUTPUT ;
    USE SIGNAL ;
    PORT
      LAYER M5 ;
        RECT  26.544 19.356 26.568 19.44 ;
    END
  END o[116]
  PIN o[117]
    DIRECTION OUTPUT ;
    USE SIGNAL ;
    PORT
      LAYER M5 ;
        RECT  26.64 19.356 26.664 19.44 ;
    END
  END o[117]
  PIN o[118]
    DIRECTION OUTPUT ;
    USE SIGNAL ;
    PORT
      LAYER M5 ;
        RECT  26.736 19.356 26.76 19.44 ;
    END
  END o[118]
  PIN o[119]
    DIRECTION OUTPUT ;
    USE SIGNAL ;
    PORT
      LAYER M5 ;
        RECT  26.832 19.356 26.856 19.44 ;
    END
  END o[119]
  PIN o[11]
    DIRECTION OUTPUT ;
    USE SIGNAL ;
    PORT
      LAYER M5 ;
        RECT  16.464 19.356 16.488 19.44 ;
    END
  END o[11]
  PIN o[120]
    DIRECTION OUTPUT ;
    USE SIGNAL ;
    PORT
      LAYER M5 ;
        RECT  26.928 19.356 26.952 19.44 ;
    END
  END o[120]
  PIN o[121]
    DIRECTION OUTPUT ;
    USE SIGNAL ;
    PORT
      LAYER M5 ;
        RECT  27.024 19.356 27.048 19.44 ;
    END
  END o[121]
  PIN o[122]
    DIRECTION OUTPUT ;
    USE SIGNAL ;
    PORT
      LAYER M5 ;
        RECT  27.12 19.356 27.144 19.44 ;
    END
  END o[122]
  PIN o[123]
    DIRECTION OUTPUT ;
    USE SIGNAL ;
    PORT
      LAYER M5 ;
        RECT  27.216 19.356 27.24 19.44 ;
    END
  END o[123]
  PIN o[124]
    DIRECTION OUTPUT ;
    USE SIGNAL ;
    PORT
      LAYER M5 ;
        RECT  27.312 19.356 27.336 19.44 ;
    END
  END o[124]
  PIN o[125]
    DIRECTION OUTPUT ;
    USE SIGNAL ;
    PORT
      LAYER M5 ;
        RECT  27.408 19.356 27.432 19.44 ;
    END
  END o[125]
  PIN o[126]
    DIRECTION OUTPUT ;
    USE SIGNAL ;
    PORT
      LAYER M5 ;
        RECT  27.504 19.356 27.528 19.44 ;
    END
  END o[126]
  PIN o[127]
    DIRECTION OUTPUT ;
    USE SIGNAL ;
    PORT
      LAYER M5 ;
        RECT  27.6 19.356 27.624 19.44 ;
    END
  END o[127]
  PIN o[128]
    DIRECTION OUTPUT ;
    USE SIGNAL ;
    PORT
      LAYER M5 ;
        RECT  18.48 19.356 18.504 19.44 ;
    END
  END o[128]
  PIN o[129]
    DIRECTION OUTPUT ;
    USE SIGNAL ;
    PORT
      LAYER M5 ;
        RECT  18.576 19.356 18.6 19.44 ;
    END
  END o[129]
  PIN o[12]
    DIRECTION OUTPUT ;
    USE SIGNAL ;
    PORT
      LAYER M5 ;
        RECT  16.56 19.356 16.584 19.44 ;
    END
  END o[12]
  PIN o[130]
    DIRECTION OUTPUT ;
    USE SIGNAL ;
    PORT
      LAYER M5 ;
        RECT  18.672 19.356 18.696 19.44 ;
    END
  END o[130]
  PIN o[131]
    DIRECTION OUTPUT ;
    USE SIGNAL ;
    PORT
      LAYER M5 ;
        RECT  18.768 19.356 18.792 19.44 ;
    END
  END o[131]
  PIN o[132]
    DIRECTION OUTPUT ;
    USE SIGNAL ;
    PORT
      LAYER M5 ;
        RECT  18.864 19.356 18.888 19.44 ;
    END
  END o[132]
  PIN o[133]
    DIRECTION OUTPUT ;
    USE SIGNAL ;
    PORT
      LAYER M5 ;
        RECT  18.96 19.356 18.984 19.44 ;
    END
  END o[133]
  PIN o[134]
    DIRECTION OUTPUT ;
    USE SIGNAL ;
    PORT
      LAYER M5 ;
        RECT  19.056 19.356 19.08 19.44 ;
    END
  END o[134]
  PIN o[135]
    DIRECTION OUTPUT ;
    USE SIGNAL ;
    PORT
      LAYER M5 ;
        RECT  19.152 19.356 19.176 19.44 ;
    END
  END o[135]
  PIN o[136]
    DIRECTION OUTPUT ;
    USE SIGNAL ;
    PORT
      LAYER M5 ;
        RECT  19.248 19.356 19.272 19.44 ;
    END
  END o[136]
  PIN o[137]
    DIRECTION OUTPUT ;
    USE SIGNAL ;
    PORT
      LAYER M5 ;
        RECT  19.344 19.356 19.368 19.44 ;
    END
  END o[137]
  PIN o[138]
    DIRECTION OUTPUT ;
    USE SIGNAL ;
    PORT
      LAYER M5 ;
        RECT  19.44 19.356 19.464 19.44 ;
    END
  END o[138]
  PIN o[139]
    DIRECTION OUTPUT ;
    USE SIGNAL ;
    PORT
      LAYER M5 ;
        RECT  19.536 19.356 19.56 19.44 ;
    END
  END o[139]
  PIN o[13]
    DIRECTION OUTPUT ;
    USE SIGNAL ;
    PORT
      LAYER M5 ;
        RECT  16.656 19.356 16.68 19.44 ;
    END
  END o[13]
  PIN o[140]
    DIRECTION OUTPUT ;
    USE SIGNAL ;
    PORT
      LAYER M5 ;
        RECT  19.632 19.356 19.656 19.44 ;
    END
  END o[140]
  PIN o[141]
    DIRECTION OUTPUT ;
    USE SIGNAL ;
    PORT
      LAYER M5 ;
        RECT  19.728 19.356 19.752 19.44 ;
    END
  END o[141]
  PIN o[142]
    DIRECTION OUTPUT ;
    USE SIGNAL ;
    PORT
      LAYER M5 ;
        RECT  19.824 19.356 19.848 19.44 ;
    END
  END o[142]
  PIN o[143]
    DIRECTION OUTPUT ;
    USE SIGNAL ;
    PORT
      LAYER M5 ;
        RECT  19.92 19.356 19.944 19.44 ;
    END
  END o[143]
  PIN o[144]
    DIRECTION OUTPUT ;
    USE SIGNAL ;
    PORT
      LAYER M5 ;
        RECT  20.016 19.356 20.04 19.44 ;
    END
  END o[144]
  PIN o[145]
    DIRECTION OUTPUT ;
    USE SIGNAL ;
    PORT
      LAYER M5 ;
        RECT  20.112 19.356 20.136 19.44 ;
    END
  END o[145]
  PIN o[146]
    DIRECTION OUTPUT ;
    USE SIGNAL ;
    PORT
      LAYER M5 ;
        RECT  20.208 19.356 20.232 19.44 ;
    END
  END o[146]
  PIN o[147]
    DIRECTION OUTPUT ;
    USE SIGNAL ;
    PORT
      LAYER M5 ;
        RECT  20.304 19.356 20.328 19.44 ;
    END
  END o[147]
  PIN o[148]
    DIRECTION OUTPUT ;
    USE SIGNAL ;
    PORT
      LAYER M5 ;
        RECT  20.4 19.356 20.424 19.44 ;
    END
  END o[148]
  PIN o[149]
    DIRECTION OUTPUT ;
    USE SIGNAL ;
    PORT
      LAYER M5 ;
        RECT  20.496 19.356 20.52 19.44 ;
    END
  END o[149]
  PIN o[14]
    DIRECTION OUTPUT ;
    USE SIGNAL ;
    PORT
      LAYER M5 ;
        RECT  16.752 19.356 16.776 19.44 ;
    END
  END o[14]
  PIN o[150]
    DIRECTION OUTPUT ;
    USE SIGNAL ;
    PORT
      LAYER M5 ;
        RECT  20.592 19.356 20.616 19.44 ;
    END
  END o[150]
  PIN o[151]
    DIRECTION OUTPUT ;
    USE SIGNAL ;
    PORT
      LAYER M5 ;
        RECT  20.688 19.356 20.712 19.44 ;
    END
  END o[151]
  PIN o[152]
    DIRECTION OUTPUT ;
    USE SIGNAL ;
    PORT
      LAYER M5 ;
        RECT  20.784 19.356 20.808 19.44 ;
    END
  END o[152]
  PIN o[153]
    DIRECTION OUTPUT ;
    USE SIGNAL ;
    PORT
      LAYER M5 ;
        RECT  20.88 19.356 20.904 19.44 ;
    END
  END o[153]
  PIN o[154]
    DIRECTION OUTPUT ;
    USE SIGNAL ;
    PORT
      LAYER M5 ;
        RECT  20.976 19.356 21 19.44 ;
    END
  END o[154]
  PIN o[155]
    DIRECTION OUTPUT ;
    USE SIGNAL ;
    PORT
      LAYER M5 ;
        RECT  21.072 19.356 21.096 19.44 ;
    END
  END o[155]
  PIN o[156]
    DIRECTION OUTPUT ;
    USE SIGNAL ;
    PORT
      LAYER M5 ;
        RECT  21.168 19.356 21.192 19.44 ;
    END
  END o[156]
  PIN o[157]
    DIRECTION OUTPUT ;
    USE SIGNAL ;
    PORT
      LAYER M5 ;
        RECT  21.264 19.356 21.288 19.44 ;
    END
  END o[157]
  PIN o[158]
    DIRECTION OUTPUT ;
    USE SIGNAL ;
    PORT
      LAYER M5 ;
        RECT  21.36 19.356 21.384 19.44 ;
    END
  END o[158]
  PIN o[159]
    DIRECTION OUTPUT ;
    USE SIGNAL ;
    PORT
      LAYER M5 ;
        RECT  21.456 19.356 21.48 19.44 ;
    END
  END o[159]
  PIN o[15]
    DIRECTION OUTPUT ;
    USE SIGNAL ;
    PORT
      LAYER M5 ;
        RECT  16.848 19.356 16.872 19.44 ;
    END
  END o[15]
  PIN o[160]
    DIRECTION OUTPUT ;
    USE SIGNAL ;
    PORT
      LAYER M5 ;
        RECT  27.696 19.356 27.72 19.44 ;
    END
  END o[160]
  PIN o[161]
    DIRECTION OUTPUT ;
    USE SIGNAL ;
    PORT
      LAYER M5 ;
        RECT  27.792 19.356 27.816 19.44 ;
    END
  END o[161]
  PIN o[162]
    DIRECTION OUTPUT ;
    USE SIGNAL ;
    PORT
      LAYER M5 ;
        RECT  27.888 19.356 27.912 19.44 ;
    END
  END o[162]
  PIN o[163]
    DIRECTION OUTPUT ;
    USE SIGNAL ;
    PORT
      LAYER M5 ;
        RECT  27.984 19.356 28.008 19.44 ;
    END
  END o[163]
  PIN o[164]
    DIRECTION OUTPUT ;
    USE SIGNAL ;
    PORT
      LAYER M5 ;
        RECT  28.08 19.356 28.104 19.44 ;
    END
  END o[164]
  PIN o[165]
    DIRECTION OUTPUT ;
    USE SIGNAL ;
    PORT
      LAYER M5 ;
        RECT  28.176 19.356 28.2 19.44 ;
    END
  END o[165]
  PIN o[166]
    DIRECTION OUTPUT ;
    USE SIGNAL ;
    PORT
      LAYER M5 ;
        RECT  28.272 19.356 28.296 19.44 ;
    END
  END o[166]
  PIN o[167]
    DIRECTION OUTPUT ;
    USE SIGNAL ;
    PORT
      LAYER M5 ;
        RECT  28.368 19.356 28.392 19.44 ;
    END
  END o[167]
  PIN o[168]
    DIRECTION OUTPUT ;
    USE SIGNAL ;
    PORT
      LAYER M5 ;
        RECT  28.464 19.356 28.488 19.44 ;
    END
  END o[168]
  PIN o[169]
    DIRECTION OUTPUT ;
    USE SIGNAL ;
    PORT
      LAYER M5 ;
        RECT  28.56 19.356 28.584 19.44 ;
    END
  END o[169]
  PIN o[16]
    DIRECTION OUTPUT ;
    USE SIGNAL ;
    PORT
      LAYER M5 ;
        RECT  16.944 19.356 16.968 19.44 ;
    END
  END o[16]
  PIN o[170]
    DIRECTION OUTPUT ;
    USE SIGNAL ;
    PORT
      LAYER M5 ;
        RECT  28.656 19.356 28.68 19.44 ;
    END
  END o[170]
  PIN o[171]
    DIRECTION OUTPUT ;
    USE SIGNAL ;
    PORT
      LAYER M5 ;
        RECT  28.752 19.356 28.776 19.44 ;
    END
  END o[171]
  PIN o[172]
    DIRECTION OUTPUT ;
    USE SIGNAL ;
    PORT
      LAYER M5 ;
        RECT  28.848 19.356 28.872 19.44 ;
    END
  END o[172]
  PIN o[173]
    DIRECTION OUTPUT ;
    USE SIGNAL ;
    PORT
      LAYER M5 ;
        RECT  28.944 19.356 28.968 19.44 ;
    END
  END o[173]
  PIN o[174]
    DIRECTION OUTPUT ;
    USE SIGNAL ;
    PORT
      LAYER M5 ;
        RECT  29.04 19.356 29.064 19.44 ;
    END
  END o[174]
  PIN o[175]
    DIRECTION OUTPUT ;
    USE SIGNAL ;
    PORT
      LAYER M5 ;
        RECT  29.136 19.356 29.16 19.44 ;
    END
  END o[175]
  PIN o[176]
    DIRECTION OUTPUT ;
    USE SIGNAL ;
    PORT
      LAYER M5 ;
        RECT  29.232 19.356 29.256 19.44 ;
    END
  END o[176]
  PIN o[177]
    DIRECTION OUTPUT ;
    USE SIGNAL ;
    PORT
      LAYER M5 ;
        RECT  29.328 19.356 29.352 19.44 ;
    END
  END o[177]
  PIN o[178]
    DIRECTION OUTPUT ;
    USE SIGNAL ;
    PORT
      LAYER M5 ;
        RECT  29.424 19.356 29.448 19.44 ;
    END
  END o[178]
  PIN o[179]
    DIRECTION OUTPUT ;
    USE SIGNAL ;
    PORT
      LAYER M5 ;
        RECT  29.52 19.356 29.544 19.44 ;
    END
  END o[179]
  PIN o[17]
    DIRECTION OUTPUT ;
    USE SIGNAL ;
    PORT
      LAYER M5 ;
        RECT  17.04 19.356 17.064 19.44 ;
    END
  END o[17]
  PIN o[180]
    DIRECTION OUTPUT ;
    USE SIGNAL ;
    PORT
      LAYER M5 ;
        RECT  29.616 19.356 29.64 19.44 ;
    END
  END o[180]
  PIN o[181]
    DIRECTION OUTPUT ;
    USE SIGNAL ;
    PORT
      LAYER M5 ;
        RECT  29.712 19.356 29.736 19.44 ;
    END
  END o[181]
  PIN o[182]
    DIRECTION OUTPUT ;
    USE SIGNAL ;
    PORT
      LAYER M5 ;
        RECT  29.808 19.356 29.832 19.44 ;
    END
  END o[182]
  PIN o[183]
    DIRECTION OUTPUT ;
    USE SIGNAL ;
    PORT
      LAYER M5 ;
        RECT  29.904 19.356 29.928 19.44 ;
    END
  END o[183]
  PIN o[184]
    DIRECTION OUTPUT ;
    USE SIGNAL ;
    PORT
      LAYER M5 ;
        RECT  30 19.356 30.024 19.44 ;
    END
  END o[184]
  PIN o[185]
    DIRECTION OUTPUT ;
    USE SIGNAL ;
    PORT
      LAYER M5 ;
        RECT  30.096 19.356 30.12 19.44 ;
    END
  END o[185]
  PIN o[186]
    DIRECTION OUTPUT ;
    USE SIGNAL ;
    PORT
      LAYER M5 ;
        RECT  30.192 19.356 30.216 19.44 ;
    END
  END o[186]
  PIN o[187]
    DIRECTION OUTPUT ;
    USE SIGNAL ;
    PORT
      LAYER M5 ;
        RECT  30.288 19.356 30.312 19.44 ;
    END
  END o[187]
  PIN o[188]
    DIRECTION OUTPUT ;
    USE SIGNAL ;
    PORT
      LAYER M5 ;
        RECT  30.384 19.356 30.408 19.44 ;
    END
  END o[188]
  PIN o[189]
    DIRECTION OUTPUT ;
    USE SIGNAL ;
    PORT
      LAYER M5 ;
        RECT  30.48 19.356 30.504 19.44 ;
    END
  END o[189]
  PIN o[18]
    DIRECTION OUTPUT ;
    USE SIGNAL ;
    PORT
      LAYER M5 ;
        RECT  17.136 19.356 17.16 19.44 ;
    END
  END o[18]
  PIN o[190]
    DIRECTION OUTPUT ;
    USE SIGNAL ;
    PORT
      LAYER M5 ;
        RECT  30.576 19.356 30.6 19.44 ;
    END
  END o[190]
  PIN o[191]
    DIRECTION OUTPUT ;
    USE SIGNAL ;
    PORT
      LAYER M5 ;
        RECT  30.672 19.356 30.696 19.44 ;
    END
  END o[191]
  PIN o[192]
    DIRECTION OUTPUT ;
    USE SIGNAL ;
    PORT
      LAYER M5 ;
        RECT  8.496 19.356 8.52 19.44 ;
    END
  END o[192]
  PIN o[193]
    DIRECTION OUTPUT ;
    USE SIGNAL ;
    PORT
      LAYER M5 ;
        RECT  8.592 19.356 8.616 19.44 ;
    END
  END o[193]
  PIN o[194]
    DIRECTION OUTPUT ;
    USE SIGNAL ;
    PORT
      LAYER M5 ;
        RECT  8.688 19.356 8.712 19.44 ;
    END
  END o[194]
  PIN o[195]
    DIRECTION OUTPUT ;
    USE SIGNAL ;
    PORT
      LAYER M5 ;
        RECT  8.784 19.356 8.808 19.44 ;
    END
  END o[195]
  PIN o[196]
    DIRECTION OUTPUT ;
    USE SIGNAL ;
    PORT
      LAYER M5 ;
        RECT  8.88 19.356 8.904 19.44 ;
    END
  END o[196]
  PIN o[197]
    DIRECTION OUTPUT ;
    USE SIGNAL ;
    PORT
      LAYER M5 ;
        RECT  8.976 19.356 9 19.44 ;
    END
  END o[197]
  PIN o[198]
    DIRECTION OUTPUT ;
    USE SIGNAL ;
    PORT
      LAYER M5 ;
        RECT  9.072 19.356 9.096 19.44 ;
    END
  END o[198]
  PIN o[199]
    DIRECTION OUTPUT ;
    USE SIGNAL ;
    PORT
      LAYER M5 ;
        RECT  9.168 19.356 9.192 19.44 ;
    END
  END o[199]
  PIN o[19]
    DIRECTION OUTPUT ;
    USE SIGNAL ;
    PORT
      LAYER M5 ;
        RECT  17.232 19.356 17.256 19.44 ;
    END
  END o[19]
  PIN o[1]
    DIRECTION OUTPUT ;
    USE SIGNAL ;
    PORT
      LAYER M5 ;
        RECT  15.504 19.356 15.528 19.44 ;
    END
  END o[1]
  PIN o[200]
    DIRECTION OUTPUT ;
    USE SIGNAL ;
    PORT
      LAYER M5 ;
        RECT  9.264 19.356 9.288 19.44 ;
    END
  END o[200]
  PIN o[201]
    DIRECTION OUTPUT ;
    USE SIGNAL ;
    PORT
      LAYER M5 ;
        RECT  9.36 19.356 9.384 19.44 ;
    END
  END o[201]
  PIN o[202]
    DIRECTION OUTPUT ;
    USE SIGNAL ;
    PORT
      LAYER M5 ;
        RECT  9.456 19.356 9.48 19.44 ;
    END
  END o[202]
  PIN o[203]
    DIRECTION OUTPUT ;
    USE SIGNAL ;
    PORT
      LAYER M5 ;
        RECT  9.552 19.356 9.576 19.44 ;
    END
  END o[203]
  PIN o[204]
    DIRECTION OUTPUT ;
    USE SIGNAL ;
    PORT
      LAYER M5 ;
        RECT  9.648 19.356 9.672 19.44 ;
    END
  END o[204]
  PIN o[205]
    DIRECTION OUTPUT ;
    USE SIGNAL ;
    PORT
      LAYER M5 ;
        RECT  9.744 19.356 9.768 19.44 ;
    END
  END o[205]
  PIN o[206]
    DIRECTION OUTPUT ;
    USE SIGNAL ;
    PORT
      LAYER M5 ;
        RECT  9.84 19.356 9.864 19.44 ;
    END
  END o[206]
  PIN o[207]
    DIRECTION OUTPUT ;
    USE SIGNAL ;
    PORT
      LAYER M5 ;
        RECT  9.936 19.356 9.96 19.44 ;
    END
  END o[207]
  PIN o[208]
    DIRECTION OUTPUT ;
    USE SIGNAL ;
    PORT
      LAYER M5 ;
        RECT  10.032 19.356 10.056 19.44 ;
    END
  END o[208]
  PIN o[209]
    DIRECTION OUTPUT ;
    USE SIGNAL ;
    PORT
      LAYER M5 ;
        RECT  10.128 19.356 10.152 19.44 ;
    END
  END o[209]
  PIN o[20]
    DIRECTION OUTPUT ;
    USE SIGNAL ;
    PORT
      LAYER M5 ;
        RECT  17.328 19.356 17.352 19.44 ;
    END
  END o[20]
  PIN o[210]
    DIRECTION OUTPUT ;
    USE SIGNAL ;
    PORT
      LAYER M5 ;
        RECT  10.224 19.356 10.248 19.44 ;
    END
  END o[210]
  PIN o[211]
    DIRECTION OUTPUT ;
    USE SIGNAL ;
    PORT
      LAYER M5 ;
        RECT  10.32 19.356 10.344 19.44 ;
    END
  END o[211]
  PIN o[212]
    DIRECTION OUTPUT ;
    USE SIGNAL ;
    PORT
      LAYER M5 ;
        RECT  10.416 19.356 10.44 19.44 ;
    END
  END o[212]
  PIN o[213]
    DIRECTION OUTPUT ;
    USE SIGNAL ;
    PORT
      LAYER M5 ;
        RECT  10.512 19.356 10.536 19.44 ;
    END
  END o[213]
  PIN o[214]
    DIRECTION OUTPUT ;
    USE SIGNAL ;
    PORT
      LAYER M5 ;
        RECT  10.608 19.356 10.632 19.44 ;
    END
  END o[214]
  PIN o[215]
    DIRECTION OUTPUT ;
    USE SIGNAL ;
    PORT
      LAYER M5 ;
        RECT  10.704 19.356 10.728 19.44 ;
    END
  END o[215]
  PIN o[216]
    DIRECTION OUTPUT ;
    USE SIGNAL ;
    PORT
      LAYER M5 ;
        RECT  10.8 19.356 10.824 19.44 ;
    END
  END o[216]
  PIN o[217]
    DIRECTION OUTPUT ;
    USE SIGNAL ;
    PORT
      LAYER M5 ;
        RECT  10.896 19.356 10.92 19.44 ;
    END
  END o[217]
  PIN o[218]
    DIRECTION OUTPUT ;
    USE SIGNAL ;
    PORT
      LAYER M5 ;
        RECT  10.992 19.356 11.016 19.44 ;
    END
  END o[218]
  PIN o[219]
    DIRECTION OUTPUT ;
    USE SIGNAL ;
    PORT
      LAYER M5 ;
        RECT  11.088 19.356 11.112 19.44 ;
    END
  END o[219]
  PIN o[21]
    DIRECTION OUTPUT ;
    USE SIGNAL ;
    PORT
      LAYER M5 ;
        RECT  17.424 19.356 17.448 19.44 ;
    END
  END o[21]
  PIN o[220]
    DIRECTION OUTPUT ;
    USE SIGNAL ;
    PORT
      LAYER M5 ;
        RECT  11.184 19.356 11.208 19.44 ;
    END
  END o[220]
  PIN o[221]
    DIRECTION OUTPUT ;
    USE SIGNAL ;
    PORT
      LAYER M5 ;
        RECT  11.28 19.356 11.304 19.44 ;
    END
  END o[221]
  PIN o[222]
    DIRECTION OUTPUT ;
    USE SIGNAL ;
    PORT
      LAYER M5 ;
        RECT  11.376 19.356 11.4 19.44 ;
    END
  END o[222]
  PIN o[223]
    DIRECTION OUTPUT ;
    USE SIGNAL ;
    PORT
      LAYER M5 ;
        RECT  11.472 19.356 11.496 19.44 ;
    END
  END o[223]
  PIN o[224]
    DIRECTION OUTPUT ;
    USE SIGNAL ;
    PORT
      LAYER M5 ;
        RECT  11.568 19.356 11.592 19.44 ;
    END
  END o[224]
  PIN o[225]
    DIRECTION OUTPUT ;
    USE SIGNAL ;
    PORT
      LAYER M5 ;
        RECT  11.664 19.356 11.688 19.44 ;
    END
  END o[225]
  PIN o[226]
    DIRECTION OUTPUT ;
    USE SIGNAL ;
    PORT
      LAYER M5 ;
        RECT  11.76 19.356 11.784 19.44 ;
    END
  END o[226]
  PIN o[227]
    DIRECTION OUTPUT ;
    USE SIGNAL ;
    PORT
      LAYER M5 ;
        RECT  11.856 19.356 11.88 19.44 ;
    END
  END o[227]
  PIN o[228]
    DIRECTION OUTPUT ;
    USE SIGNAL ;
    PORT
      LAYER M5 ;
        RECT  11.952 19.356 11.976 19.44 ;
    END
  END o[228]
  PIN o[229]
    DIRECTION OUTPUT ;
    USE SIGNAL ;
    PORT
      LAYER M5 ;
        RECT  12.048 19.356 12.072 19.44 ;
    END
  END o[229]
  PIN o[22]
    DIRECTION OUTPUT ;
    USE SIGNAL ;
    PORT
      LAYER M5 ;
        RECT  17.52 19.356 17.544 19.44 ;
    END
  END o[22]
  PIN o[230]
    DIRECTION OUTPUT ;
    USE SIGNAL ;
    PORT
      LAYER M5 ;
        RECT  12.144 19.356 12.168 19.44 ;
    END
  END o[230]
  PIN o[231]
    DIRECTION OUTPUT ;
    USE SIGNAL ;
    PORT
      LAYER M5 ;
        RECT  12.24 19.356 12.264 19.44 ;
    END
  END o[231]
  PIN o[232]
    DIRECTION OUTPUT ;
    USE SIGNAL ;
    PORT
      LAYER M5 ;
        RECT  12.336 19.356 12.36 19.44 ;
    END
  END o[232]
  PIN o[233]
    DIRECTION OUTPUT ;
    USE SIGNAL ;
    PORT
      LAYER M5 ;
        RECT  12.432 19.356 12.456 19.44 ;
    END
  END o[233]
  PIN o[234]
    DIRECTION OUTPUT ;
    USE SIGNAL ;
    PORT
      LAYER M5 ;
        RECT  12.528 19.356 12.552 19.44 ;
    END
  END o[234]
  PIN o[235]
    DIRECTION OUTPUT ;
    USE SIGNAL ;
    PORT
      LAYER M5 ;
        RECT  12.624 19.356 12.648 19.44 ;
    END
  END o[235]
  PIN o[236]
    DIRECTION OUTPUT ;
    USE SIGNAL ;
    PORT
      LAYER M5 ;
        RECT  12.72 19.356 12.744 19.44 ;
    END
  END o[236]
  PIN o[237]
    DIRECTION OUTPUT ;
    USE SIGNAL ;
    PORT
      LAYER M5 ;
        RECT  12.816 19.356 12.84 19.44 ;
    END
  END o[237]
  PIN o[238]
    DIRECTION OUTPUT ;
    USE SIGNAL ;
    PORT
      LAYER M5 ;
        RECT  12.912 19.356 12.936 19.44 ;
    END
  END o[238]
  PIN o[239]
    DIRECTION OUTPUT ;
    USE SIGNAL ;
    PORT
      LAYER M5 ;
        RECT  13.008 19.356 13.032 19.44 ;
    END
  END o[239]
  PIN o[23]
    DIRECTION OUTPUT ;
    USE SIGNAL ;
    PORT
      LAYER M5 ;
        RECT  17.616 19.356 17.64 19.44 ;
    END
  END o[23]
  PIN o[240]
    DIRECTION OUTPUT ;
    USE SIGNAL ;
    PORT
      LAYER M5 ;
        RECT  13.104 19.356 13.128 19.44 ;
    END
  END o[240]
  PIN o[241]
    DIRECTION OUTPUT ;
    USE SIGNAL ;
    PORT
      LAYER M5 ;
        RECT  13.2 19.356 13.224 19.44 ;
    END
  END o[241]
  PIN o[242]
    DIRECTION OUTPUT ;
    USE SIGNAL ;
    PORT
      LAYER M5 ;
        RECT  13.296 19.356 13.32 19.44 ;
    END
  END o[242]
  PIN o[243]
    DIRECTION OUTPUT ;
    USE SIGNAL ;
    PORT
      LAYER M5 ;
        RECT  13.392 19.356 13.416 19.44 ;
    END
  END o[243]
  PIN o[244]
    DIRECTION OUTPUT ;
    USE SIGNAL ;
    PORT
      LAYER M5 ;
        RECT  13.488 19.356 13.512 19.44 ;
    END
  END o[244]
  PIN o[245]
    DIRECTION OUTPUT ;
    USE SIGNAL ;
    PORT
      LAYER M5 ;
        RECT  13.584 19.356 13.608 19.44 ;
    END
  END o[245]
  PIN o[246]
    DIRECTION OUTPUT ;
    USE SIGNAL ;
    PORT
      LAYER M5 ;
        RECT  13.68 19.356 13.704 19.44 ;
    END
  END o[246]
  PIN o[247]
    DIRECTION OUTPUT ;
    USE SIGNAL ;
    PORT
      LAYER M5 ;
        RECT  13.776 19.356 13.8 19.44 ;
    END
  END o[247]
  PIN o[248]
    DIRECTION OUTPUT ;
    USE SIGNAL ;
    PORT
      LAYER M5 ;
        RECT  13.872 19.356 13.896 19.44 ;
    END
  END o[248]
  PIN o[249]
    DIRECTION OUTPUT ;
    USE SIGNAL ;
    PORT
      LAYER M5 ;
        RECT  13.968 19.356 13.992 19.44 ;
    END
  END o[249]
  PIN o[24]
    DIRECTION OUTPUT ;
    USE SIGNAL ;
    PORT
      LAYER M5 ;
        RECT  17.712 19.356 17.736 19.44 ;
    END
  END o[24]
  PIN o[250]
    DIRECTION OUTPUT ;
    USE SIGNAL ;
    PORT
      LAYER M5 ;
        RECT  14.064 19.356 14.088 19.44 ;
    END
  END o[250]
  PIN o[251]
    DIRECTION OUTPUT ;
    USE SIGNAL ;
    PORT
      LAYER M5 ;
        RECT  14.16 19.356 14.184 19.44 ;
    END
  END o[251]
  PIN o[252]
    DIRECTION OUTPUT ;
    USE SIGNAL ;
    PORT
      LAYER M5 ;
        RECT  14.256 19.356 14.28 19.44 ;
    END
  END o[252]
  PIN o[253]
    DIRECTION OUTPUT ;
    USE SIGNAL ;
    PORT
      LAYER M5 ;
        RECT  14.352 19.356 14.376 19.44 ;
    END
  END o[253]
  PIN o[254]
    DIRECTION OUTPUT ;
    USE SIGNAL ;
    PORT
      LAYER M5 ;
        RECT  14.448 19.356 14.472 19.44 ;
    END
  END o[254]
  PIN o[255]
    DIRECTION OUTPUT ;
    USE SIGNAL ;
    PORT
      LAYER M5 ;
        RECT  14.544 19.356 14.568 19.44 ;
    END
  END o[255]
  PIN o[256]
    DIRECTION OUTPUT ;
    USE SIGNAL ;
    PORT
      LAYER M5 ;
        RECT  7.536 19.356 7.56 19.44 ;
    END
  END o[256]
  PIN o[257]
    DIRECTION OUTPUT ;
    USE SIGNAL ;
    PORT
      LAYER M5 ;
        RECT  7.632 19.356 7.656 19.44 ;
    END
  END o[257]
  PIN o[258]
    DIRECTION OUTPUT ;
    USE SIGNAL ;
    PORT
      LAYER M5 ;
        RECT  7.728 19.356 7.752 19.44 ;
    END
  END o[258]
  PIN o[259]
    DIRECTION OUTPUT ;
    USE SIGNAL ;
    PORT
      LAYER M5 ;
        RECT  7.824 19.356 7.848 19.44 ;
    END
  END o[259]
  PIN o[25]
    DIRECTION OUTPUT ;
    USE SIGNAL ;
    PORT
      LAYER M5 ;
        RECT  17.808 19.356 17.832 19.44 ;
    END
  END o[25]
  PIN o[260]
    DIRECTION OUTPUT ;
    USE SIGNAL ;
    PORT
      LAYER M5 ;
        RECT  7.92 19.356 7.944 19.44 ;
    END
  END o[260]
  PIN o[261]
    DIRECTION OUTPUT ;
    USE SIGNAL ;
    PORT
      LAYER M5 ;
        RECT  8.016 19.356 8.04 19.44 ;
    END
  END o[261]
  PIN o[262]
    DIRECTION OUTPUT ;
    USE SIGNAL ;
    PORT
      LAYER M5 ;
        RECT  8.112 19.356 8.136 19.44 ;
    END
  END o[262]
  PIN o[263]
    DIRECTION OUTPUT ;
    USE SIGNAL ;
    PORT
      LAYER M5 ;
        RECT  8.208 19.356 8.232 19.44 ;
    END
  END o[263]
  PIN o[264]
    DIRECTION OUTPUT ;
    USE SIGNAL ;
    PORT
      LAYER M5 ;
        RECT  8.304 19.356 8.328 19.44 ;
    END
  END o[264]
  PIN o[265]
    DIRECTION OUTPUT ;
    USE SIGNAL ;
    PORT
      LAYER M5 ;
        RECT  8.4 19.356 8.424 19.44 ;
    END
  END o[265]
  PIN o[26]
    DIRECTION OUTPUT ;
    USE SIGNAL ;
    PORT
      LAYER M5 ;
        RECT  17.904 19.356 17.928 19.44 ;
    END
  END o[26]
  PIN o[27]
    DIRECTION OUTPUT ;
    USE SIGNAL ;
    PORT
      LAYER M5 ;
        RECT  18 19.356 18.024 19.44 ;
    END
  END o[27]
  PIN o[28]
    DIRECTION OUTPUT ;
    USE SIGNAL ;
    PORT
      LAYER M5 ;
        RECT  18.096 19.356 18.12 19.44 ;
    END
  END o[28]
  PIN o[29]
    DIRECTION OUTPUT ;
    USE SIGNAL ;
    PORT
      LAYER M5 ;
        RECT  18.192 19.356 18.216 19.44 ;
    END
  END o[29]
  PIN o[2]
    DIRECTION OUTPUT ;
    USE SIGNAL ;
    PORT
      LAYER M5 ;
        RECT  15.6 19.356 15.624 19.44 ;
    END
  END o[2]
  PIN o[30]
    DIRECTION OUTPUT ;
    USE SIGNAL ;
    PORT
      LAYER M5 ;
        RECT  18.288 19.356 18.312 19.44 ;
    END
  END o[30]
  PIN o[31]
    DIRECTION OUTPUT ;
    USE SIGNAL ;
    PORT
      LAYER M5 ;
        RECT  18.384 19.356 18.408 19.44 ;
    END
  END o[31]
  PIN o[32]
    DIRECTION OUTPUT ;
    USE SIGNAL ;
    PORT
      LAYER M5 ;
        RECT  21.552 19.356 21.576 19.44 ;
    END
  END o[32]
  PIN o[33]
    DIRECTION OUTPUT ;
    USE SIGNAL ;
    PORT
      LAYER M5 ;
        RECT  21.648 19.356 21.672 19.44 ;
    END
  END o[33]
  PIN o[34]
    DIRECTION OUTPUT ;
    USE SIGNAL ;
    PORT
      LAYER M5 ;
        RECT  21.744 19.356 21.768 19.44 ;
    END
  END o[34]
  PIN o[35]
    DIRECTION OUTPUT ;
    USE SIGNAL ;
    PORT
      LAYER M5 ;
        RECT  21.84 19.356 21.864 19.44 ;
    END
  END o[35]
  PIN o[36]
    DIRECTION OUTPUT ;
    USE SIGNAL ;
    PORT
      LAYER M5 ;
        RECT  21.936 19.356 21.96 19.44 ;
    END
  END o[36]
  PIN o[37]
    DIRECTION OUTPUT ;
    USE SIGNAL ;
    PORT
      LAYER M5 ;
        RECT  22.032 19.356 22.056 19.44 ;
    END
  END o[37]
  PIN o[38]
    DIRECTION OUTPUT ;
    USE SIGNAL ;
    PORT
      LAYER M5 ;
        RECT  22.128 19.356 22.152 19.44 ;
    END
  END o[38]
  PIN o[39]
    DIRECTION OUTPUT ;
    USE SIGNAL ;
    PORT
      LAYER M5 ;
        RECT  22.224 19.356 22.248 19.44 ;
    END
  END o[39]
  PIN o[3]
    DIRECTION OUTPUT ;
    USE SIGNAL ;
    PORT
      LAYER M5 ;
        RECT  15.696 19.356 15.72 19.44 ;
    END
  END o[3]
  PIN o[40]
    DIRECTION OUTPUT ;
    USE SIGNAL ;
    PORT
      LAYER M5 ;
        RECT  22.32 19.356 22.344 19.44 ;
    END
  END o[40]
  PIN o[41]
    DIRECTION OUTPUT ;
    USE SIGNAL ;
    PORT
      LAYER M5 ;
        RECT  22.416 19.356 22.44 19.44 ;
    END
  END o[41]
  PIN o[42]
    DIRECTION OUTPUT ;
    USE SIGNAL ;
    PORT
      LAYER M5 ;
        RECT  22.512 19.356 22.536 19.44 ;
    END
  END o[42]
  PIN o[43]
    DIRECTION OUTPUT ;
    USE SIGNAL ;
    PORT
      LAYER M5 ;
        RECT  22.608 19.356 22.632 19.44 ;
    END
  END o[43]
  PIN o[44]
    DIRECTION OUTPUT ;
    USE SIGNAL ;
    PORT
      LAYER M5 ;
        RECT  22.704 19.356 22.728 19.44 ;
    END
  END o[44]
  PIN o[45]
    DIRECTION OUTPUT ;
    USE SIGNAL ;
    PORT
      LAYER M5 ;
        RECT  22.8 19.356 22.824 19.44 ;
    END
  END o[45]
  PIN o[46]
    DIRECTION OUTPUT ;
    USE SIGNAL ;
    PORT
      LAYER M5 ;
        RECT  22.896 19.356 22.92 19.44 ;
    END
  END o[46]
  PIN o[47]
    DIRECTION OUTPUT ;
    USE SIGNAL ;
    PORT
      LAYER M5 ;
        RECT  22.992 19.356 23.016 19.44 ;
    END
  END o[47]
  PIN o[48]
    DIRECTION OUTPUT ;
    USE SIGNAL ;
    PORT
      LAYER M5 ;
        RECT  23.088 19.356 23.112 19.44 ;
    END
  END o[48]
  PIN o[49]
    DIRECTION OUTPUT ;
    USE SIGNAL ;
    PORT
      LAYER M5 ;
        RECT  23.184 19.356 23.208 19.44 ;
    END
  END o[49]
  PIN o[4]
    DIRECTION OUTPUT ;
    USE SIGNAL ;
    PORT
      LAYER M5 ;
        RECT  15.792 19.356 15.816 19.44 ;
    END
  END o[4]
  PIN o[50]
    DIRECTION OUTPUT ;
    USE SIGNAL ;
    PORT
      LAYER M5 ;
        RECT  23.28 19.356 23.304 19.44 ;
    END
  END o[50]
  PIN o[51]
    DIRECTION OUTPUT ;
    USE SIGNAL ;
    PORT
      LAYER M5 ;
        RECT  23.376 19.356 23.4 19.44 ;
    END
  END o[51]
  PIN o[52]
    DIRECTION OUTPUT ;
    USE SIGNAL ;
    PORT
      LAYER M5 ;
        RECT  23.472 19.356 23.496 19.44 ;
    END
  END o[52]
  PIN o[53]
    DIRECTION OUTPUT ;
    USE SIGNAL ;
    PORT
      LAYER M5 ;
        RECT  23.568 19.356 23.592 19.44 ;
    END
  END o[53]
  PIN o[54]
    DIRECTION OUTPUT ;
    USE SIGNAL ;
    PORT
      LAYER M5 ;
        RECT  23.664 19.356 23.688 19.44 ;
    END
  END o[54]
  PIN o[55]
    DIRECTION OUTPUT ;
    USE SIGNAL ;
    PORT
      LAYER M5 ;
        RECT  23.76 19.356 23.784 19.44 ;
    END
  END o[55]
  PIN o[56]
    DIRECTION OUTPUT ;
    USE SIGNAL ;
    PORT
      LAYER M5 ;
        RECT  23.856 19.356 23.88 19.44 ;
    END
  END o[56]
  PIN o[57]
    DIRECTION OUTPUT ;
    USE SIGNAL ;
    PORT
      LAYER M5 ;
        RECT  23.952 19.356 23.976 19.44 ;
    END
  END o[57]
  PIN o[58]
    DIRECTION OUTPUT ;
    USE SIGNAL ;
    PORT
      LAYER M5 ;
        RECT  24.048 19.356 24.072 19.44 ;
    END
  END o[58]
  PIN o[59]
    DIRECTION OUTPUT ;
    USE SIGNAL ;
    PORT
      LAYER M5 ;
        RECT  24.144 19.356 24.168 19.44 ;
    END
  END o[59]
  PIN o[5]
    DIRECTION OUTPUT ;
    USE SIGNAL ;
    PORT
      LAYER M5 ;
        RECT  15.888 19.356 15.912 19.44 ;
    END
  END o[5]
  PIN o[60]
    DIRECTION OUTPUT ;
    USE SIGNAL ;
    PORT
      LAYER M5 ;
        RECT  24.24 19.356 24.264 19.44 ;
    END
  END o[60]
  PIN o[61]
    DIRECTION OUTPUT ;
    USE SIGNAL ;
    PORT
      LAYER M5 ;
        RECT  24.336 19.356 24.36 19.44 ;
    END
  END o[61]
  PIN o[62]
    DIRECTION OUTPUT ;
    USE SIGNAL ;
    PORT
      LAYER M5 ;
        RECT  24.432 19.356 24.456 19.44 ;
    END
  END o[62]
  PIN o[63]
    DIRECTION OUTPUT ;
    USE SIGNAL ;
    PORT
      LAYER M5 ;
        RECT  24.528 19.356 24.552 19.44 ;
    END
  END o[63]
  PIN o[64]
    DIRECTION OUTPUT ;
    USE SIGNAL ;
    PORT
      LAYER M5 ;
        RECT  30.768 19.356 30.792 19.44 ;
    END
  END o[64]
  PIN o[65]
    DIRECTION OUTPUT ;
    USE SIGNAL ;
    PORT
      LAYER M5 ;
        RECT  30.864 19.356 30.888 19.44 ;
    END
  END o[65]
  PIN o[66]
    DIRECTION OUTPUT ;
    USE SIGNAL ;
    PORT
      LAYER M5 ;
        RECT  30.96 19.356 30.984 19.44 ;
    END
  END o[66]
  PIN o[67]
    DIRECTION OUTPUT ;
    USE SIGNAL ;
    PORT
      LAYER M5 ;
        RECT  31.056 19.356 31.08 19.44 ;
    END
  END o[67]
  PIN o[68]
    DIRECTION OUTPUT ;
    USE SIGNAL ;
    PORT
      LAYER M5 ;
        RECT  31.152 19.356 31.176 19.44 ;
    END
  END o[68]
  PIN o[69]
    DIRECTION OUTPUT ;
    USE SIGNAL ;
    PORT
      LAYER M5 ;
        RECT  31.248 19.356 31.272 19.44 ;
    END
  END o[69]
  PIN o[6]
    DIRECTION OUTPUT ;
    USE SIGNAL ;
    PORT
      LAYER M5 ;
        RECT  15.984 19.356 16.008 19.44 ;
    END
  END o[6]
  PIN o[70]
    DIRECTION OUTPUT ;
    USE SIGNAL ;
    PORT
      LAYER M5 ;
        RECT  31.344 19.356 31.368 19.44 ;
    END
  END o[70]
  PIN o[71]
    DIRECTION OUTPUT ;
    USE SIGNAL ;
    PORT
      LAYER M5 ;
        RECT  31.44 19.356 31.464 19.44 ;
    END
  END o[71]
  PIN o[72]
    DIRECTION OUTPUT ;
    USE SIGNAL ;
    PORT
      LAYER M5 ;
        RECT  31.536 19.356 31.56 19.44 ;
    END
  END o[72]
  PIN o[73]
    DIRECTION OUTPUT ;
    USE SIGNAL ;
    PORT
      LAYER M5 ;
        RECT  31.632 19.356 31.656 19.44 ;
    END
  END o[73]
  PIN o[74]
    DIRECTION OUTPUT ;
    USE SIGNAL ;
    PORT
      LAYER M5 ;
        RECT  31.728 19.356 31.752 19.44 ;
    END
  END o[74]
  PIN o[75]
    DIRECTION OUTPUT ;
    USE SIGNAL ;
    PORT
      LAYER M5 ;
        RECT  31.824 19.356 31.848 19.44 ;
    END
  END o[75]
  PIN o[76]
    DIRECTION OUTPUT ;
    USE SIGNAL ;
    PORT
      LAYER M5 ;
        RECT  31.92 19.356 31.944 19.44 ;
    END
  END o[76]
  PIN o[77]
    DIRECTION OUTPUT ;
    USE SIGNAL ;
    PORT
      LAYER M5 ;
        RECT  32.016 19.356 32.04 19.44 ;
    END
  END o[77]
  PIN o[78]
    DIRECTION OUTPUT ;
    USE SIGNAL ;
    PORT
      LAYER M5 ;
        RECT  32.112 19.356 32.136 19.44 ;
    END
  END o[78]
  PIN o[79]
    DIRECTION OUTPUT ;
    USE SIGNAL ;
    PORT
      LAYER M5 ;
        RECT  32.208 19.356 32.232 19.44 ;
    END
  END o[79]
  PIN o[7]
    DIRECTION OUTPUT ;
    USE SIGNAL ;
    PORT
      LAYER M5 ;
        RECT  16.08 19.356 16.104 19.44 ;
    END
  END o[7]
  PIN o[80]
    DIRECTION OUTPUT ;
    USE SIGNAL ;
    PORT
      LAYER M5 ;
        RECT  32.304 19.356 32.328 19.44 ;
    END
  END o[80]
  PIN o[81]
    DIRECTION OUTPUT ;
    USE SIGNAL ;
    PORT
      LAYER M5 ;
        RECT  32.4 19.356 32.424 19.44 ;
    END
  END o[81]
  PIN o[82]
    DIRECTION OUTPUT ;
    USE SIGNAL ;
    PORT
      LAYER M5 ;
        RECT  32.496 19.356 32.52 19.44 ;
    END
  END o[82]
  PIN o[83]
    DIRECTION OUTPUT ;
    USE SIGNAL ;
    PORT
      LAYER M5 ;
        RECT  32.592 19.356 32.616 19.44 ;
    END
  END o[83]
  PIN o[84]
    DIRECTION OUTPUT ;
    USE SIGNAL ;
    PORT
      LAYER M5 ;
        RECT  32.688 19.356 32.712 19.44 ;
    END
  END o[84]
  PIN o[85]
    DIRECTION OUTPUT ;
    USE SIGNAL ;
    PORT
      LAYER M5 ;
        RECT  32.784 19.356 32.808 19.44 ;
    END
  END o[85]
  PIN o[86]
    DIRECTION OUTPUT ;
    USE SIGNAL ;
    PORT
      LAYER M5 ;
        RECT  32.88 19.356 32.904 19.44 ;
    END
  END o[86]
  PIN o[87]
    DIRECTION OUTPUT ;
    USE SIGNAL ;
    PORT
      LAYER M5 ;
        RECT  32.976 19.356 33 19.44 ;
    END
  END o[87]
  PIN o[88]
    DIRECTION OUTPUT ;
    USE SIGNAL ;
    PORT
      LAYER M5 ;
        RECT  33.072 19.356 33.096 19.44 ;
    END
  END o[88]
  PIN o[89]
    DIRECTION OUTPUT ;
    USE SIGNAL ;
    PORT
      LAYER M5 ;
        RECT  33.168 19.356 33.192 19.44 ;
    END
  END o[89]
  PIN o[8]
    DIRECTION OUTPUT ;
    USE SIGNAL ;
    PORT
      LAYER M5 ;
        RECT  16.176 19.356 16.2 19.44 ;
    END
  END o[8]
  PIN o[90]
    DIRECTION OUTPUT ;
    USE SIGNAL ;
    PORT
      LAYER M5 ;
        RECT  33.264 19.356 33.288 19.44 ;
    END
  END o[90]
  PIN o[91]
    DIRECTION OUTPUT ;
    USE SIGNAL ;
    PORT
      LAYER M5 ;
        RECT  33.36 19.356 33.384 19.44 ;
    END
  END o[91]
  PIN o[92]
    DIRECTION OUTPUT ;
    USE SIGNAL ;
    PORT
      LAYER M5 ;
        RECT  33.456 19.356 33.48 19.44 ;
    END
  END o[92]
  PIN o[93]
    DIRECTION OUTPUT ;
    USE SIGNAL ;
    PORT
      LAYER M5 ;
        RECT  33.552 19.356 33.576 19.44 ;
    END
  END o[93]
  PIN o[94]
    DIRECTION OUTPUT ;
    USE SIGNAL ;
    PORT
      LAYER M5 ;
        RECT  33.648 19.356 33.672 19.44 ;
    END
  END o[94]
  PIN o[95]
    DIRECTION OUTPUT ;
    USE SIGNAL ;
    PORT
      LAYER M5 ;
        RECT  33.744 19.356 33.768 19.44 ;
    END
  END o[95]
  PIN o[96]
    DIRECTION OUTPUT ;
    USE SIGNAL ;
    PORT
      LAYER M5 ;
        RECT  24.624 19.356 24.648 19.44 ;
    END
  END o[96]
  PIN o[97]
    DIRECTION OUTPUT ;
    USE SIGNAL ;
    PORT
      LAYER M5 ;
        RECT  24.72 19.356 24.744 19.44 ;
    END
  END o[97]
  PIN o[98]
    DIRECTION OUTPUT ;
    USE SIGNAL ;
    PORT
      LAYER M5 ;
        RECT  24.816 19.356 24.84 19.44 ;
    END
  END o[98]
  PIN o[99]
    DIRECTION OUTPUT ;
    USE SIGNAL ;
    PORT
      LAYER M5 ;
        RECT  24.912 19.356 24.936 19.44 ;
    END
  END o[99]
  PIN o[9]
    DIRECTION OUTPUT ;
    USE SIGNAL ;
    PORT
      LAYER M5 ;
        RECT  16.272 19.356 16.296 19.44 ;
    END
  END o[9]
  PIN rs
    DIRECTION INPUT ;
    USE SIGNAL ;
    PORT
      LAYER M4 ;
        RECT  34.476 3.12 34.56 3.144 ;
    END
  END rs
  PIN VDD
    DIRECTION INOUT ;
    USE POWER ;
    PORT
      LAYER M5 ;
        RECT  29.592 2.151 29.712 17.289 ;
        RECT  24.192 2.151 24.312 17.289 ;
        RECT  18.792 2.151 18.912 17.289 ;
        RECT  13.392 2.151 13.512 17.289 ;
        RECT  7.992 2.151 8.112 17.289 ;
        RECT  2.592 2.151 2.712 17.289 ;
    END
  END VDD
  PIN VSS
    DIRECTION INOUT ;
    USE GROUND ;
    PORT
      LAYER M5 ;
        RECT  29.4 2.137 29.52 17.303 ;
        RECT  24 2.137 24.12 17.303 ;
        RECT  18.6 2.137 18.72 17.303 ;
        RECT  13.2 2.137 13.32 17.303 ;
        RECT  7.8 2.137 7.92 17.303 ;
        RECT  2.4 2.137 2.52 17.303 ;
    END
  END VSS
  OBS
    LAYER RVTN ;
     RECT  2.16 2.16 32.4 2.295 ;
     RECT  2.16 2.565 32.4 2.835 ;
     RECT  2.16 3.105 32.4 3.375 ;
     RECT  2.16 3.645 32.4 3.915 ;
     RECT  2.16 4.185 32.4 4.455 ;
     RECT  2.16 4.725 32.4 4.995 ;
     RECT  2.16 5.265 32.4 5.535 ;
     RECT  2.16 5.805 32.4 6.075 ;
     RECT  2.16 6.345 32.4 6.615 ;
     RECT  2.16 6.885 32.4 7.155 ;
     RECT  2.16 7.425 32.4 7.695 ;
     RECT  2.16 7.965 32.4 8.235 ;
     RECT  2.16 8.505 32.4 8.775 ;
     RECT  2.16 9.045 32.4 9.315 ;
     RECT  2.16 9.585 32.4 9.855 ;
     RECT  2.16 10.125 32.4 10.395 ;
     RECT  2.16 10.665 32.4 10.935 ;
     RECT  2.16 11.205 32.4 11.475 ;
     RECT  2.16 11.745 32.4 12.015 ;
     RECT  2.16 12.285 32.4 12.555 ;
     RECT  2.16 12.825 32.4 13.095 ;
     RECT  2.16 13.365 32.4 13.635 ;
     RECT  2.16 13.905 32.4 14.175 ;
     RECT  2.16 14.445 32.4 14.715 ;
     RECT  2.16 14.985 32.4 15.255 ;
     RECT  2.16 15.525 32.4 15.795 ;
     RECT  2.16 16.065 32.4 16.335 ;
     RECT  2.16 16.605 32.4 16.875 ;
     RECT  2.16 17.145 32.4 17.28 ;
    LAYER RVTP ;
     RECT  2.16 2.295 32.4 2.565 ;
     RECT  2.16 2.835 32.4 3.105 ;
     RECT  2.16 3.375 32.4 3.645 ;
     RECT  2.16 3.915 32.4 4.185 ;
     RECT  2.16 4.455 32.4 4.725 ;
     RECT  2.16 4.995 32.4 5.265 ;
     RECT  2.16 5.535 32.4 5.805 ;
     RECT  2.16 6.075 32.4 6.345 ;
     RECT  2.16 6.615 32.4 6.885 ;
     RECT  2.16 7.155 32.4 7.425 ;
     RECT  2.16 7.695 32.4 7.965 ;
     RECT  2.16 8.235 32.4 8.505 ;
     RECT  2.16 8.775 32.4 9.045 ;
     RECT  2.16 9.315 32.4 9.585 ;
     RECT  2.16 9.855 32.4 10.125 ;
     RECT  2.16 10.395 32.4 10.665 ;
     RECT  2.16 10.935 32.4 11.205 ;
     RECT  2.16 11.475 32.4 11.745 ;
     RECT  2.16 12.015 32.4 12.285 ;
     RECT  2.16 12.555 32.4 12.825 ;
     RECT  2.16 13.095 32.4 13.365 ;
     RECT  2.16 13.635 32.4 13.905 ;
     RECT  2.16 14.175 32.4 14.445 ;
     RECT  2.16 14.715 32.4 14.985 ;
     RECT  2.16 15.255 32.4 15.525 ;
     RECT  2.16 15.795 32.4 16.065 ;
     RECT  2.16 16.335 32.4 16.605 ;
     RECT  2.16 16.875 32.4 17.145 ;
    LAYER M1 ;
     RECT  2.16 2.151 32.4 17.289 ;
    LAYER M2 ;
     RECT  1.147 4.932 1.399 4.95 ;
     RECT  1.507 3.042 1.615 3.06 ;
     RECT  1.399 4.662 1.795 4.95 ;
     RECT  1.795 4.392 1.975 4.95 ;
     RECT  1.687 2.232 2.16 2.25 ;
     RECT  1.615 3.042 2.16 3.33 ;
     RECT  1.975 4.194 2.16 4.95 ;
     RECT  2.16 2.151 2.191 17.289 ;
     RECT  2.191 2.106 3.127 17.289 ;
     RECT  3.127 1.998 5.683 17.289 ;
     RECT  5.683 1.962 6.871 17.289 ;
     RECT  6.871 1.881 7.231 17.289 ;
     RECT  7.555 18.774 7.655 18.792 ;
     RECT  12.379 0.846 14.683 0.864 ;
     RECT  7.231 1.692 14.683 17.289 ;
     RECT  15.223 0.072 15.331 0.09 ;
     RECT  15.331 0.036 15.619 0.09 ;
     RECT  14.683 0.846 15.619 17.289 ;
     RECT  15.619 0.036 21.191 17.289 ;
     RECT  21.191 0.036 21.947 0.198 ;
     RECT  21.191 1.422 22.127 17.289 ;
     RECT  21.947 0.036 22.307 0.09 ;
     RECT  22.307 0.036 22.559 0.054 ;
     RECT  26.095 18.774 26.231 18.792 ;
     RECT  22.127 1.692 26.879 17.289 ;
     RECT  26.879 1.962 27.563 17.289 ;
     RECT  27.563 2.151 32.4 17.289 ;
     RECT  32.4 14.796 32.423 16.902 ;
     RECT  32.423 14.796 32.531 14.814 ;
     RECT  32.4 9.396 32.567 12.546 ;
     RECT  32.423 15.876 32.567 16.902 ;
     RECT  32.567 9.594 32.603 12.546 ;
     RECT  32.567 15.876 32.603 16.704 ;
     RECT  32.4 4.536 32.711 4.644 ;
     RECT  32.603 15.876 32.711 16.434 ;
     RECT  32.603 9.936 33.107 12.546 ;
     RECT  32.711 4.626 33.143 4.644 ;
     RECT  32.711 15.876 33.143 16.164 ;
     RECT  32.4 7.974 33.179 7.992 ;
     RECT  33.143 16.146 33.179 16.164 ;
     RECT  33.107 10.566 33.215 12.546 ;
     RECT  33.215 11.106 33.323 12.546 ;
     RECT  33.323 11.556 33.575 12.546 ;
     RECT  32.4 3.312 33.611 3.33 ;
     RECT  33.575 11.556 33.683 12.114 ;
     RECT  33.683 11.556 33.791 11.574 ;
    LAYER M3 ;
     RECT  15.336 0.031 15.354 0.067 ;
     RECT  22.536 0.031 22.554 0.067 ;
     RECT  15.228 0.067 15.354 0.091 ;
     RECT  22.284 0.067 22.554 0.091 ;
     RECT  18.828 0.091 18.846 0.139 ;
     RECT  15.228 0.091 15.534 0.175 ;
     RECT  22.284 0.091 23.49 0.175 ;
     RECT  18.828 0.139 18.99 0.317 ;
     RECT  18.9 0.317 18.99 0.365 ;
     RECT  18.972 0.365 18.99 0.461 ;
     RECT  21.924 0.175 23.49 0.523 ;
     RECT  25.668 0.091 25.974 0.523 ;
     RECT  4.86 0.523 4.878 0.571 ;
     RECT  5.724 0.523 6.246 0.571 ;
     RECT  21.924 0.523 23.67 0.571 ;
     RECT  12.456 0.811 12.474 0.841 ;
     RECT  15.228 0.175 15.642 0.859 ;
     RECT  15.228 0.859 15.93 0.877 ;
     RECT  20.088 0.091 21.186 0.905 ;
     RECT  20.088 0.905 21.114 0.907 ;
     RECT  25.668 0.523 26.442 1.099 ;
     RECT  25.128 1.099 26.442 1.147 ;
     RECT  12.384 0.841 12.474 1.387 ;
     RECT  15.048 0.877 15.93 1.453 ;
     RECT  14.688 1.453 15.93 1.483 ;
     RECT  14.688 1.483 16.542 1.531 ;
     RECT  18.792 1.099 18.81 1.675 ;
     RECT  19.98 0.907 21.114 1.675 ;
     RECT  4.86 0.571 6.966 1.687 ;
     RECT  4.104 1.147 4.122 1.723 ;
     RECT  4.86 1.687 7.254 1.723 ;
     RECT  8.136 1.243 8.154 1.723 ;
     RECT  12.384 1.387 12.978 1.723 ;
     RECT  14.544 1.531 16.542 1.723 ;
     RECT  18.792 1.675 21.114 1.723 ;
     RECT  21.924 0.571 24.174 1.723 ;
     RECT  25.128 1.147 26.946 1.723 ;
     RECT  1.692 1.723 10.17 1.771 ;
     RECT  11.088 1.723 11.574 1.771 ;
     RECT  12.384 1.723 26.946 1.771 ;
     RECT  1.692 1.771 10.242 1.819 ;
     RECT  11.088 1.771 26.946 1.819 ;
     RECT  1.692 1.819 26.946 1.957 ;
     RECT  29.415 2.143 29.505 2.299 ;
     RECT  29.415 2.299 29.79 2.371 ;
     RECT  1.692 1.957 27.558 2.497 ;
     RECT  28.8 2.371 29.79 2.497 ;
     RECT  1.692 2.497 27.63 2.533 ;
     RECT  28.8 2.497 30.222 2.533 ;
     RECT  31.104 2.497 31.122 2.533 ;
     RECT  1.692 2.533 27.666 2.641 ;
     RECT  28.8 2.533 31.122 2.641 ;
     RECT  1.692 2.641 31.518 2.923 ;
     RECT  1.512 2.923 31.518 3.065 ;
     RECT  33.48 3.019 33.498 3.115 ;
     RECT  33.48 3.115 33.606 3.149 ;
     RECT  1.62 3.065 31.518 3.335 ;
     RECT  33.588 3.149 33.606 3.335 ;
     RECT  1.8 3.335 31.518 3.721 ;
     RECT  1.8 3.721 31.734 4.415 ;
     RECT  32.688 4.531 32.706 4.621 ;
     RECT  1.152 4.603 1.422 4.685 ;
     RECT  1.152 4.685 1.17 4.955 ;
     RECT  2.232 4.415 31.734 6.241 ;
     RECT  32.688 4.621 33.138 6.241 ;
     RECT  2.232 6.241 33.138 6.449 ;
     RECT  2.304 6.449 33.138 7.115 ;
     RECT  2.415 7.115 33.138 7.969 ;
     RECT  2.415 7.969 33.174 10.561 ;
     RECT  2.415 10.561 33.21 11.101 ;
     RECT  2.415 11.101 33.318 11.551 ;
     RECT  2.415 11.551 33.786 14.369 ;
     RECT  2.415 14.369 2.97 14.405 ;
     RECT  3.708 14.369 33.786 14.675 ;
     RECT  3.924 14.675 33.786 15.403 ;
     RECT  3.564 15.403 33.786 15.449 ;
     RECT  3.852 15.449 33.786 15.791 ;
     RECT  4.212 15.791 33.786 16.439 ;
     RECT  4.212 16.439 4.518 16.799 ;
     RECT  2.415 14.405 2.697 17.027 ;
     RECT  5.292 16.439 33.786 17.069 ;
     RECT  5.976 17.069 6.318 17.105 ;
     RECT  7.164 17.069 28.602 17.105 ;
     RECT  6.3 17.105 6.318 17.141 ;
     RECT  7.524 17.105 28.494 17.177 ;
     RECT  2.415 17.027 2.505 17.297 ;
     RECT  29.415 17.069 33.786 17.297 ;
     RECT  29.772 17.297 33.786 17.405 ;
     RECT  15.516 17.177 28.494 17.501 ;
     RECT  15.516 17.501 18.774 17.549 ;
     RECT  15.516 17.549 18.522 17.645 ;
     RECT  19.584 17.501 28.494 17.645 ;
     RECT  29.988 17.405 33.786 17.645 ;
     RECT  22.464 17.645 28.422 17.693 ;
     RECT  22.5 17.693 28.422 17.741 ;
     RECT  7.524 17.177 14.706 18.221 ;
     RECT  15.516 17.645 16.866 18.221 ;
     RECT  22.5 17.741 23.922 18.221 ;
     RECT  24.696 17.741 28.422 18.221 ;
     RECT  30.816 17.645 33.786 18.221 ;
     RECT  10.332 18.221 14.526 18.269 ;
     RECT  16.668 18.221 16.866 18.269 ;
     RECT  27.648 18.221 28.314 18.269 ;
     RECT  10.332 18.269 13.194 18.317 ;
     RECT  15.516 18.221 15.894 18.749 ;
     RECT  30.816 18.221 31.446 18.749 ;
     RECT  9.36 18.221 9.486 18.797 ;
     RECT  10.332 18.317 12.942 18.797 ;
     RECT  14.148 18.269 14.526 18.797 ;
     RECT  15.516 18.749 15.534 18.797 ;
     RECT  21.672 17.645 21.69 18.797 ;
     RECT  22.824 18.221 23.922 18.797 ;
     RECT  24.696 18.221 26.658 18.797 ;
     RECT  27.864 18.269 28.314 18.797 ;
     RECT  7.524 18.221 8.406 18.845 ;
     RECT  20.628 17.645 20.682 18.845 ;
     RECT  24.696 18.797 26.226 18.845 ;
     RECT  30.852 18.749 31.446 18.845 ;
     RECT  7.632 18.845 8.226 18.893 ;
     RECT  28.296 18.797 28.314 18.893 ;
     RECT  19.224 19.099 19.242 19.147 ;
     RECT  29.988 17.645 30.042 19.181 ;
     RECT  7.776 18.893 8.226 19.277 ;
     RECT  9.396 18.797 9.486 19.277 ;
     RECT  19.116 19.147 19.242 19.277 ;
     RECT  32.616 18.221 33.786 19.277 ;
     RECT  7.776 19.277 8.154 19.325 ;
     RECT  9.396 19.277 9.414 19.325 ;
     RECT  11.592 18.797 11.61 19.325 ;
     RECT  12.42 18.797 12.438 19.325 ;
     RECT  16.668 18.269 16.686 19.325 ;
     RECT  17.64 17.645 18.162 19.325 ;
     RECT  19.116 19.277 19.134 19.325 ;
     RECT  20.664 18.845 20.682 19.325 ;
     RECT  22.824 18.797 23.562 19.325 ;
     RECT  24.696 18.845 25.434 19.325 ;
     RECT  29.988 19.181 30.006 19.325 ;
     RECT  31.428 18.845 31.446 19.325 ;
     RECT  32.616 19.277 33.678 19.325 ;
    LAYER M4 ;
     RECT  0.709 2.304 0.805 2.328 ;
     RECT  0.805 2.304 0.901 2.616 ;
     RECT  0.997 4.56 1.093 4.584 ;
     RECT  1.093 4.56 1.189 4.632 ;
     RECT  0.901 2.304 1.285 2.904 ;
     RECT  1.189 4.56 1.285 5.16 ;
     RECT  1.285 2.304 1.637 5.16 ;
     RECT  1.637 1.728 2.408 5.16 ;
     RECT  2.408 1.728 2.512 17.292 ;
     RECT  2.512 1.728 2.704 17.022 ;
     RECT  2.704 4.128 2.909 4.152 ;
     RECT  2.704 6.672 3.769 7.176 ;
     RECT  2.704 11.952 3.773 12.552 ;
     RECT  3.769 6.672 3.877 7.896 ;
     RECT  2.704 1.728 3.949 2.904 ;
     RECT  2.704 15.408 3.973 15.432 ;
     RECT  3.949 1.728 4.049 3.624 ;
     RECT  4.049 1.152 4.133 3.624 ;
     RECT  3.973 14.928 4.169 15.432 ;
     RECT  3.877 5.856 4.345 7.896 ;
     RECT  2.704 13.872 4.745 13.896 ;
     RECT  4.345 5.856 4.849 8.088 ;
     RECT  2.704 9.264 4.849 9.288 ;
     RECT  4.133 1.728 5.065 3.624 ;
     RECT  4.849 5.856 5.101 9.288 ;
     RECT  2.704 10.704 5.141 10.728 ;
     RECT  4.849 0.528 5.173 0.552 ;
     RECT  5.029 13.92 5.389 13.944 ;
     RECT  4.169 14.928 5.389 14.952 ;
     RECT  5.317 15.984 5.425 16.008 ;
     RECT  5.065 1.728 5.461 3.816 ;
     RECT  5.461 1.728 5.509 4.296 ;
     RECT  5.509 1.728 5.533 4.536 ;
     RECT  5.533 1.728 5.641 4.632 ;
     RECT  5.389 13.92 5.753 14.952 ;
     RECT  5.641 1.68 5.785 4.632 ;
     RECT  5.101 5.712 5.785 9.288 ;
     RECT  5.785 1.68 5.857 9.288 ;
     RECT  5.173 0.528 5.948 0.6 ;
     RECT  5.857 1.68 5.948 9.336 ;
     RECT  3.773 12.528 6.073 12.552 ;
     RECT  5.753 13.92 6.077 14.856 ;
     RECT  6.073 12.528 6.133 12.6 ;
     RECT  6.077 14.256 6.179 14.856 ;
     RECT  5.569 11.376 6.181 11.4 ;
     RECT  6.133 12.384 6.181 12.6 ;
     RECT  5.425 15.984 6.217 16.968 ;
     RECT  6.181 11.376 6.265 12.6 ;
     RECT  5.948 0.528 6.329 9.336 ;
     RECT  6.265 12.528 6.581 12.6 ;
     RECT  6.179 14.304 6.617 14.856 ;
     RECT  6.265 11.376 6.685 11.4 ;
     RECT  6.329 0.528 6.707 9.24 ;
     RECT  6.685 10.608 6.761 11.4 ;
     RECT  6.761 10.608 6.829 11.16 ;
     RECT  6.707 0.576 6.913 9.24 ;
     RECT  6.913 0.576 7.021 0.6 ;
     RECT  6.973 12.816 7.225 12.84 ;
     RECT  7.225 12.816 7.297 12.888 ;
     RECT  6.617 14.304 7.297 14.328 ;
     RECT  6.217 15.888 7.333 16.968 ;
     RECT  7.297 12.816 7.621 14.328 ;
     RECT  7.333 15.744 7.621 16.968 ;
     RECT  7.484 18.816 7.621 18.84 ;
     RECT  7.621 12.816 7.685 17.448 ;
     RECT  6.913 1.728 7.808 9.24 ;
     RECT  6.829 10.416 7.808 11.16 ;
     RECT  7.685 12.816 7.808 17.64 ;
     RECT  7.808 1.728 7.955 17.64 ;
     RECT  7.955 1.728 8.005 17.112 ;
     RECT  8.005 1.248 8.104 17.112 ;
     RECT  8.104 1.248 8.165 9.24 ;
     RECT  7.621 18.816 8.165 19.32 ;
     RECT  8.165 18.816 8.237 19.272 ;
     RECT  8.237 18.816 8.243 18.888 ;
     RECT  8.243 18.816 8.581 18.84 ;
     RECT  8.104 10.416 9.053 17.112 ;
     RECT  8.581 18.144 9.053 18.84 ;
     RECT  8.165 1.728 9.169 9.24 ;
     RECT  9.053 10.416 9.169 18.84 ;
     RECT  9.169 1.728 9.341 18.84 ;
     RECT  9.341 1.728 9.425 19.32 ;
     RECT  9.425 1.728 9.965 19.272 ;
     RECT  9.965 18.72 10.115 19.272 ;
     RECT  10.115 18.72 10.961 18.792 ;
     RECT  9.965 1.728 11.257 17.688 ;
     RECT  10.961 18.672 11.257 18.792 ;
     RECT  11.257 1.728 11.461 18.792 ;
     RECT  11.461 1.728 12.445 19.32 ;
     RECT  12.445 0.816 12.449 19.32 ;
     RECT  12.449 0.816 13.381 19.272 ;
     RECT  13.381 0.336 13.429 19.272 ;
     RECT  13.429 0.144 13.619 19.272 ;
     RECT  13.619 0.336 13.667 19.272 ;
     RECT  13.667 0.816 13.673 18.792 ;
     RECT  13.673 15.216 13.997 18.792 ;
     RECT  13.997 15.552 14.483 18.792 ;
     RECT  13.673 0.816 14.537 13.848 ;
     RECT  14.537 0.816 14.629 13.656 ;
     RECT  14.483 15.552 15.077 17.16 ;
     RECT  15.077 15.552 15.185 15.576 ;
     RECT  14.629 0.096 15.617 13.656 ;
     RECT  15.617 0.096 15.689 13.608 ;
     RECT  15.077 17.136 15.781 17.16 ;
     RECT  14.483 18.192 15.781 18.792 ;
     RECT  15.781 17.136 15.905 18.792 ;
     RECT  15.973 19.248 16.259 19.272 ;
     RECT  16.181 14.784 16.265 14.808 ;
     RECT  16.069 15.984 16.301 16.008 ;
     RECT  15.905 17.136 16.357 18.264 ;
     RECT  16.801 15.216 16.913 15.384 ;
     RECT  16.913 15.216 16.949 15.24 ;
     RECT  15.689 0.096 16.981 13.416 ;
     RECT  16.981 0.096 17.365 14.232 ;
     RECT  17.365 0.096 17.411 14.712 ;
     RECT  16.357 16.512 17.747 18.264 ;
     RECT  16.613 19.296 17.948 19.32 ;
     RECT  17.411 14.64 18.061 14.712 ;
     RECT  18.061 14.64 18.181 15.048 ;
     RECT  17.411 0.096 18.373 13.416 ;
     RECT  17.747 16.512 18.533 17.64 ;
     RECT  18.373 0.096 18.608 13.656 ;
     RECT  18.181 14.64 18.608 15.384 ;
     RECT  18.533 16.512 18.608 17.544 ;
     RECT  18.608 0.096 18.857 17.544 ;
     RECT  17.948 18.816 18.901 19.32 ;
     RECT  18.857 0.144 19.001 17.544 ;
     RECT  18.901 18.768 19.043 19.32 ;
     RECT  19.001 0.24 19.091 17.544 ;
     RECT  19.043 19.008 19.091 19.32 ;
     RECT  19.091 19.104 19.189 19.32 ;
     RECT  19.189 19.104 19.253 19.272 ;
     RECT  19.253 19.152 19.283 19.272 ;
     RECT  19.283 19.248 19.297 19.272 ;
     RECT  19.091 17.088 19.525 17.544 ;
     RECT  19.091 0.24 19.613 16.104 ;
     RECT  19.613 0.24 20.077 13.416 ;
     RECT  19.613 14.688 20.243 16.104 ;
     RECT  19.525 17.088 20.473 17.64 ;
     RECT  20.581 19.296 20.617 19.32 ;
     RECT  20.243 14.688 20.693 15.432 ;
     RECT  20.617 18.816 20.693 19.32 ;
     RECT  20.077 0.096 20.725 13.416 ;
     RECT  20.693 14.832 20.915 15.432 ;
     RECT  20.693 18.816 20.915 18.84 ;
     RECT  20.725 0.096 21.085 13.656 ;
     RECT  20.915 15.024 21.197 15.432 ;
     RECT  21.085 0.096 21.241 13.8 ;
     RECT  21.241 0.144 21.305 13.8 ;
     RECT  21.305 0.144 21.395 13.704 ;
     RECT  20.473 16.512 21.541 17.64 ;
     RECT  21.617 18.768 21.701 18.792 ;
     RECT  21.197 15.024 21.773 15.048 ;
     RECT  21.395 0.192 21.779 13.704 ;
     RECT  21.779 0.192 21.875 13.416 ;
     RECT  21.541 16.032 22.133 17.64 ;
     RECT  22.133 16.08 22.213 17.64 ;
     RECT  22.213 16.08 22.405 17.688 ;
     RECT  22.405 16.08 22.529 18.216 ;
     RECT  22.165 14.832 22.597 14.856 ;
     RECT  21.875 0.288 22.849 13.416 ;
     RECT  22.789 19.296 22.875 19.32 ;
     RECT  22.849 0.096 22.885 13.416 ;
     RECT  22.597 14.784 23.077 14.856 ;
     RECT  22.529 16.08 23.173 17.736 ;
     RECT  23.077 14.784 23.281 14.952 ;
     RECT  23.173 15.984 23.281 17.736 ;
     RECT  23.281 14.784 23.525 17.736 ;
     RECT  22.885 0.096 23.545 13.704 ;
     RECT  23.545 0.528 23.653 13.704 ;
     RECT  23.653 0.528 23.699 13.8 ;
     RECT  23.699 0.576 23.701 13.8 ;
     RECT  23.525 14.784 23.701 18.216 ;
     RECT  23.701 0.576 23.749 18.216 ;
     RECT  22.875 19.248 23.749 19.32 ;
     RECT  23.749 0.576 23.897 19.32 ;
     RECT  23.897 18.768 23.933 19.32 ;
     RECT  23.897 0.576 24.185 17.736 ;
     RECT  23.933 19.248 24.419 19.32 ;
     RECT  24.185 1.104 25.093 17.736 ;
     RECT  25.093 1.104 25.409 18.264 ;
     RECT  24.419 19.296 25.445 19.32 ;
     RECT  25.409 1.104 25.517 17.16 ;
     RECT  25.517 1.104 25.523 7.368 ;
     RECT  25.657 0.096 25.729 0.12 ;
     RECT  25.409 18.24 25.765 18.264 ;
     RECT  25.517 8.976 25.955 17.16 ;
     RECT  25.523 1.728 25.985 7.368 ;
     RECT  25.955 9.024 25.985 17.16 ;
     RECT  25.985 7.344 26.021 7.368 ;
     RECT  25.729 0.096 26.029 0.696 ;
     RECT  25.985 9.12 26.413 17.16 ;
     RECT  25.765 18.24 26.413 18.84 ;
     RECT  26.029 0.528 26.483 0.696 ;
     RECT  26.413 9.12 26.525 18.84 ;
     RECT  26.525 9.888 26.771 18.84 ;
     RECT  25.985 1.728 26.849 6.024 ;
     RECT  26.483 0.672 26.867 0.696 ;
     RECT  26.771 9.888 26.885 18.264 ;
     RECT  26.885 10.032 26.957 18.264 ;
     RECT  26.917 1.152 27.001 1.176 ;
     RECT  26.849 2.784 27.065 6.024 ;
     RECT  27.061 7.44 27.241 7.464 ;
     RECT  26.957 11.04 27.281 18.264 ;
     RECT  27.065 4.128 27.317 6.024 ;
     RECT  27.241 7.44 27.325 7.992 ;
     RECT  26.957 10.032 27.389 10.056 ;
     RECT  27.317 4.128 27.497 4.248 ;
     RECT  27.281 11.04 27.569 14.28 ;
     RECT  27.397 19.248 27.683 19.272 ;
     RECT  27.065 2.784 27.713 3.144 ;
     RECT  27.281 15.408 27.781 18.264 ;
     RECT  27.325 7.44 27.827 7.464 ;
     RECT  27.317 6 28.181 6.024 ;
     RECT  27.781 15.408 28.421 18.888 ;
     RECT  28.421 15.36 28.433 18.888 ;
     RECT  28.433 15.36 28.505 17.64 ;
     RECT  27.569 11.232 28.981 14.28 ;
     RECT  28.505 15.36 28.981 17.544 ;
     RECT  27.713 2.88 29.029 3.144 ;
     RECT  27.497 4.128 29.029 4.152 ;
     RECT  28.861 6.72 29.077 6.744 ;
     RECT  28.433 18.864 29.173 18.888 ;
     RECT  29.029 2.88 29.269 4.152 ;
     RECT  28.465 5.664 29.269 5.688 ;
     RECT  28.981 11.232 29.269 17.544 ;
     RECT  29.269 2.88 29.408 5.688 ;
     RECT  29.077 6.72 29.408 6.84 ;
     RECT  28.393 7.92 29.408 7.944 ;
     RECT  29.269 10.704 29.408 17.544 ;
     RECT  29.408 2.148 29.512 17.544 ;
     RECT  29.512 2.418 29.704 17.544 ;
     RECT  29.704 2.88 29.765 3.144 ;
     RECT  29.173 18.864 29.797 19.272 ;
     RECT  29.797 18.864 30.017 19.32 ;
     RECT  30.017 18.864 30.083 19.272 ;
     RECT  29.704 11.232 30.265 17.544 ;
     RECT  30.083 18.864 30.741 18.888 ;
     RECT  29.704 8.496 30.755 8.52 ;
     RECT  30.265 11.232 30.803 17.64 ;
     RECT  30.949 4.512 31.033 4.536 ;
     RECT  30.733 6 31.057 6.024 ;
     RECT  30.803 11.904 31.129 17.64 ;
     RECT  30.741 18.72 31.129 18.888 ;
     RECT  31.129 11.904 31.139 18.888 ;
     RECT  31.057 5.088 31.141 6.024 ;
     RECT  31.139 15.984 31.241 18.888 ;
     RECT  31.241 18.192 31.333 18.888 ;
     RECT  31.333 18.192 31.457 19.32 ;
     RECT  31.457 18.192 31.475 18.888 ;
     RECT  29.765 3.12 31.705 3.144 ;
     RECT  31.241 15.984 31.763 17.064 ;
     RECT  31.705 3.12 31.789 3.912 ;
     RECT  30.956 10.848 31.811 10.872 ;
     RECT  31.763 16.176 31.817 17.064 ;
     RECT  31.139 11.904 31.859 14.856 ;
     RECT  31.859 12 31.997 14.856 ;
     RECT  31.141 6 32.003 6.024 ;
     RECT  31.997 14.832 32.003 14.856 ;
     RECT  31.997 12 32.051 13.704 ;
     RECT  31.475 18.192 32.185 18.216 ;
     RECT  32.137 9.072 32.221 9.096 ;
     RECT  32.051 12.336 32.243 13.704 ;
     RECT  32.245 10.944 32.339 10.968 ;
     RECT  32.243 13.68 32.435 13.704 ;
     RECT  31.817 17.04 32.497 17.064 ;
     RECT  32.243 12.336 32.531 12.36 ;
     RECT  32.561 19.296 32.644 19.32 ;
     RECT  32.497 17.04 32.681 17.16 ;
     RECT  32.681 17.136 32.819 17.16 ;
     RECT  32.749 18.24 32.924 18.264 ;
     RECT  32.644 19.248 32.924 19.32 ;
     RECT  32.924 18.24 33.395 19.32 ;
     RECT  31.789 3.12 33.469 3.144 ;
     RECT  33.395 18.816 33.587 19.32 ;
     RECT  33.587 19.248 33.689 19.32 ;
     RECT  33.689 19.248 33.797 19.272 ;
     RECT  33.469 3.024 34.524 3.144 ;
    LAYER M5 ;
     RECT  0.72 0.016 26.952 1.187 ;
     RECT  0.72 1.187 26.76 1.427 ;
     RECT  20.208 1.427 26.76 1.763 ;
     RECT  23.856 1.763 26.76 1.811 ;
     RECT  0.72 1.427 19.08 1.859 ;
     RECT  23.856 1.811 26.184 1.859 ;
     RECT  0.72 1.859 18.912 1.907 ;
     RECT  29.4 2.137 29.52 2.151 ;
     RECT  0.72 1.907 14.664 2.291 ;
     RECT  20.208 1.763 22.344 2.291 ;
     RECT  24 1.859 26.184 2.291 ;
     RECT  0.72 2.291 4.2 2.339 ;
     RECT  20.208 2.291 20.808 2.339 ;
     RECT  20.208 2.339 20.328 2.387 ;
     RECT  0.816 2.339 4.008 2.627 ;
     RECT  20.208 2.387 20.232 2.821 ;
     RECT  0.912 2.627 4.008 2.915 ;
     RECT  10.608 2.291 14.664 2.915 ;
     RECT  22.032 2.291 22.344 2.915 ;
     RECT  15.696 1.907 18.912 3.059 ;
     RECT  16.368 3.059 18.912 3.299 ;
     RECT  29.4 2.151 29.712 3.397 ;
     RECT  22.32 2.915 22.344 3.443 ;
     RECT  24 2.291 25.032 3.829 ;
     RECT  20.112 2.821 20.232 3.875 ;
     RECT  7.44 2.291 9.576 4.019 ;
     RECT  10.704 2.915 14.664 4.019 ;
     RECT  16.368 3.299 17.448 4.019 ;
     RECT  23.136 3.829 25.032 4.019 ;
     RECT  11.616 4.019 14.376 4.067 ;
     RECT  1.008 2.915 2.712 4.163 ;
     RECT  11.616 4.067 13.992 4.259 ;
     RECT  17.232 4.019 17.448 4.309 ;
     RECT  18.432 3.299 18.912 4.309 ;
     RECT  12.24 4.259 13.992 4.355 ;
     RECT  20.208 3.875 20.232 4.499 ;
     RECT  5.568 2.291 6.12 4.501 ;
     RECT  31.728 3.877 31.752 4.501 ;
     RECT  1.008 4.163 1.416 4.595 ;
     RECT  1.104 4.595 1.416 4.643 ;
     RECT  12.24 4.355 13.608 4.643 ;
     RECT  26.064 3.397 26.088 4.691 ;
     RECT  5.52 4.501 6.12 5.077 ;
     RECT  23.136 4.019 24.456 5.077 ;
     RECT  1.2 4.643 1.224 5.171 ;
     RECT  26.784 5.077 26.808 5.747 ;
     RECT  30.96 4.501 31.752 5.989 ;
     RECT  21.024 5.845 21.048 6.083 ;
     RECT  5.52 5.077 6.504 6.181 ;
     RECT  13.2 4.643 13.512 6.229 ;
     RECT  7.8 4.019 9.576 6.323 ;
     RECT  9.36 6.323 9.576 6.613 ;
     RECT  9.36 6.613 9.96 6.755 ;
     RECT  21.168 7.141 21.192 7.379 ;
     RECT  17.232 4.309 18.912 7.427 ;
     RECT  18.6 7.427 18.912 7.669 ;
     RECT  20.544 7.381 21.096 7.669 ;
     RECT  22.896 5.077 24.456 7.715 ;
     RECT  22.896 7.715 24.312 7.765 ;
     RECT  18.6 7.669 21.096 7.955 ;
     RECT  27.792 7.429 27.816 7.957 ;
     RECT  17.232 7.427 17.256 8.053 ;
     RECT  20.544 7.955 21.096 8.147 ;
     RECT  16.8 8.053 17.256 8.243 ;
     RECT  5.328 6.181 6.504 8.437 ;
     RECT  17.232 8.243 17.256 8.485 ;
     RECT  18.6 7.955 18.912 8.485 ;
     RECT  30.96 5.989 31.992 8.485 ;
     RECT  22.368 7.765 24.312 8.579 ;
     RECT  22.464 8.579 24.312 9.059 ;
     RECT  30.72 8.485 31.992 9.061 ;
     RECT  17.232 8.485 18.912 9.155 ;
     RECT  21.072 8.147 21.096 9.155 ;
     RECT  5.328 8.437 6.648 9.251 ;
     RECT  18.192 9.155 18.912 9.251 ;
     RECT  22.896 9.059 24.312 10.261 ;
     RECT  12.816 6.229 13.512 10.355 ;
     RECT  13.104 10.355 13.512 10.357 ;
     RECT  9.36 6.755 9.384 10.789 ;
     RECT  30.72 9.061 32.184 10.933 ;
     RECT  11.136 9.685 11.16 10.981 ;
     RECT  18.6 9.251 18.912 11.077 ;
     RECT  9.36 10.789 9.72 11.125 ;
     RECT  10.944 10.981 11.16 11.125 ;
     RECT  25.92 8.965 25.944 11.173 ;
     RECT  27.264 7.957 27.816 11.173 ;
     RECT  9.36 11.125 11.16 11.365 ;
     RECT  29.04 3.397 29.712 11.365 ;
     RECT  30.72 10.933 32.328 11.365 ;
     RECT  9.36 11.365 11.976 11.941 ;
     RECT  13.104 10.357 13.608 11.941 ;
     RECT  22.896 10.261 24.936 11.941 ;
     RECT  29.04 11.365 32.328 11.941 ;
     RECT  16.8 11.269 16.824 11.987 ;
     RECT  22.176 11.941 24.936 11.989 ;
     RECT  25.92 11.173 27.816 11.989 ;
     RECT  28.8 11.941 32.328 11.989 ;
     RECT  5.328 9.251 6.216 12.035 ;
     RECT  22.176 11.989 32.328 12.325 ;
     RECT  20.832 11.941 20.856 12.469 ;
     RECT  18.6 11.077 19.176 12.517 ;
     RECT  20.832 12.469 21.144 12.517 ;
     RECT  22.176 12.325 32.52 12.517 ;
     RECT  18.6 12.517 32.52 12.611 ;
     RECT  9.36 11.941 13.608 12.757 ;
     RECT  7.8 6.323 8.112 13.045 ;
     RECT  9.36 12.757 13.848 13.045 ;
     RECT  17.088 12.997 17.112 13.093 ;
     RECT  7.8 13.045 13.848 13.285 ;
     RECT  7.536 13.285 13.848 13.381 ;
     RECT  18.6 12.611 21.576 13.621 ;
     RECT  18.384 13.621 21.576 13.669 ;
     RECT  22.896 12.611 32.52 13.715 ;
     RECT  16.992 13.093 17.112 13.909 ;
     RECT  7.536 13.381 14.28 14.003 ;
     RECT  16.992 13.909 17.4 14.243 ;
     RECT  5.328 12.035 6.168 14.293 ;
     RECT  7.8 14.003 14.28 14.483 ;
     RECT  17.376 14.243 17.4 14.629 ;
     RECT  18.384 13.669 21.768 14.629 ;
     RECT  17.376 14.629 21.768 14.723 ;
     RECT  18.192 14.723 21.768 14.773 ;
     RECT  23.088 13.715 32.52 14.773 ;
     RECT  5.328 14.293 6.312 14.819 ;
     RECT  3.984 13.861 4.008 14.963 ;
     RECT  7.8 14.483 10.248 15.635 ;
     RECT  7.8 15.635 10.152 15.827 ;
     RECT  16.224 14.773 16.248 15.973 ;
     RECT  5.328 14.819 5.352 16.019 ;
     RECT  18.192 14.773 32.52 16.019 ;
     RECT  16.08 15.973 16.248 16.501 ;
     RECT  18.192 16.019 19.272 16.501 ;
     RECT  16.08 16.501 17.064 16.549 ;
     RECT  18.096 16.501 19.272 16.549 ;
     RECT  16.08 16.549 19.272 17.077 ;
     RECT  20.496 16.019 32.52 17.077 ;
     RECT  7.8 15.827 10.104 17.125 ;
     RECT  11.232 14.483 14.28 17.125 ;
     RECT  16.08 17.077 32.52 17.125 ;
     RECT  2.4 4.163 2.712 17.289 ;
     RECT  2.4 17.289 2.52 17.303 ;
     RECT  7.8 17.125 14.28 17.605 ;
     RECT  7.728 17.605 14.376 17.701 ;
     RECT  15.408 17.125 32.808 17.701 ;
     RECT  7.728 17.701 32.808 18.229 ;
     RECT  7.728 18.229 33.384 18.805 ;
     RECT  7.536 18.805 33.576 19.237 ;
     RECT  7.536 19.237 33.768 19.408 ;
  END
END dsfd_rly_266_SN
END LIBRARY
